VERSION 5.8 ;
BUSBITCHARS "[]" ;
DIVIDERCHAR "/" ;
UNITS
    DATABASE MICRONS 1000 ;
END UNITS

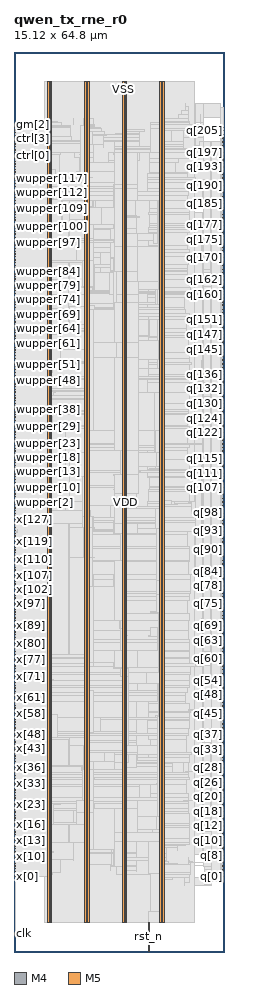
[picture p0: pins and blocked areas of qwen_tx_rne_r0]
MACRO qwen_tx_rne_r0
  FOREIGN qwen_tx_rne_r0 0 0 ;
  CLASS BLOCK ;
  SIZE 15.12 BY 64.8 ;
  PIN clk
    DIRECTION INPUT ;
    USE SIGNAL ;
    PORT
      LAYER M4 ;
        RECT  0.054 1.296 0.138 1.32 ;
    END
    PORT
      LAYER M4 ;
        RECT  0.108 1.296 0.227 1.416 ;
    END
  END clk
  PIN ctrl[0]
    DIRECTION INPUT ;
    USE SIGNAL ;
    PORT
      LAYER M4 ;
        RECT  0.054 57.36 0.138 57.384 ;
    END
  END ctrl[0]
  PIN ctrl[1]
    DIRECTION INPUT ;
    USE SIGNAL ;
    PORT
      LAYER M4 ;
        RECT  0.054 57.552 0.138 57.576 ;
    END
  END ctrl[1]
  PIN ctrl[2]
    DIRECTION INPUT ;
    USE SIGNAL ;
    PORT
      LAYER M4 ;
        RECT  0.054 57.744 0.138 57.768 ;
    END
  END ctrl[2]
  PIN ctrl[3]
    DIRECTION INPUT ;
    USE SIGNAL ;
    PORT
      LAYER M4 ;
        RECT  0.054 57.984 0.138 58.008 ;
    END
  END ctrl[3]
  PIN ctrl[4]
    DIRECTION INPUT ;
    USE SIGNAL ;
    PORT
      LAYER M4 ;
        RECT  0.054 58.176 0.138 58.2 ;
    END
  END ctrl[4]
  PIN ctrl[5]
    DIRECTION INPUT ;
    USE SIGNAL ;
    PORT
      LAYER M4 ;
        RECT  0.054 58.368 0.138 58.392 ;
    END
  END ctrl[5]
  PIN gm[0]
    DIRECTION INPUT ;
    USE SIGNAL ;
    PORT
      LAYER M4 ;
        RECT  0.054 58.56 0.138 58.584 ;
    END
  END gm[0]
  PIN gm[1]
    DIRECTION INPUT ;
    USE SIGNAL ;
    PORT
      LAYER M4 ;
        RECT  0.054 58.8 0.138 58.824 ;
    END
  END gm[1]
  PIN gm[2]
    DIRECTION INPUT ;
    USE SIGNAL ;
    PORT
      LAYER M4 ;
        RECT  0.054 58.992 0.138 59.016 ;
    END
  END gm[2]
  PIN gm[3]
    DIRECTION INPUT ;
    USE SIGNAL ;
    PORT
      LAYER M4 ;
        RECT  0.054 59.184 0.138 59.208 ;
    END
  END gm[3]
  PIN q[0]
    DIRECTION OUTPUT ;
    USE SIGNAL ;
    PORT
      LAYER M4 ;
        RECT  14.982 5.424 15.066 5.448 ;
    END
  END q[0]
  PIN q[100]
    DIRECTION OUTPUT ;
    USE SIGNAL ;
    PORT
      LAYER M4 ;
        RECT  14.982 31.584 15.066 31.608 ;
    END
  END q[100]
  PIN q[101]
    DIRECTION OUTPUT ;
    USE SIGNAL ;
    PORT
      LAYER M4 ;
        RECT  14.982 31.872 15.066 31.896 ;
    END
  END q[101]
  PIN q[102]
    DIRECTION OUTPUT ;
    USE SIGNAL ;
    PORT
      LAYER M4 ;
        RECT  14.982 32.112 15.066 32.136 ;
    END
  END q[102]
  PIN q[103]
    DIRECTION OUTPUT ;
    USE SIGNAL ;
    PORT
      LAYER M4 ;
        RECT  14.982 32.4 15.066 32.424 ;
    END
  END q[103]
  PIN q[104]
    DIRECTION OUTPUT ;
    USE SIGNAL ;
    PORT
      LAYER M4 ;
        RECT  14.982 32.64 15.066 32.664 ;
    END
  END q[104]
  PIN q[105]
    DIRECTION OUTPUT ;
    USE SIGNAL ;
    PORT
      LAYER M4 ;
        RECT  14.982 32.928 15.066 32.952 ;
    END
  END q[105]
  PIN q[106]
    DIRECTION OUTPUT ;
    USE SIGNAL ;
    PORT
      LAYER M4 ;
        RECT  14.982 33.168 15.066 33.192 ;
    END
  END q[106]
  PIN q[107]
    DIRECTION OUTPUT ;
    USE SIGNAL ;
    PORT
      LAYER M4 ;
        RECT  14.982 33.456 15.066 33.48 ;
    END
  END q[107]
  PIN q[108]
    DIRECTION OUTPUT ;
    USE SIGNAL ;
    PORT
      LAYER M4 ;
        RECT  14.982 33.696 15.066 33.72 ;
    END
  END q[108]
  PIN q[109]
    DIRECTION OUTPUT ;
    USE SIGNAL ;
    PORT
      LAYER M4 ;
        RECT  14.982 33.984 15.066 34.008 ;
    END
  END q[109]
  PIN q[10]
    DIRECTION OUTPUT ;
    USE SIGNAL ;
    PORT
      LAYER M4 ;
        RECT  14.982 8.016 15.066 8.04 ;
    END
  END q[10]
  PIN q[110]
    DIRECTION OUTPUT ;
    USE SIGNAL ;
    PORT
      LAYER M4 ;
        RECT  14.982 34.224 15.066 34.248 ;
    END
  END q[110]
  PIN q[111]
    DIRECTION OUTPUT ;
    USE SIGNAL ;
    PORT
      LAYER M4 ;
        RECT  14.982 34.464 15.066 34.488 ;
    END
  END q[111]
  PIN q[112]
    DIRECTION OUTPUT ;
    USE SIGNAL ;
    PORT
      LAYER M4 ;
        RECT  14.982 34.752 15.066 34.776 ;
    END
  END q[112]
  PIN q[113]
    DIRECTION OUTPUT ;
    USE SIGNAL ;
    PORT
      LAYER M4 ;
        RECT  14.982 34.992 15.066 35.016 ;
    END
  END q[113]
  PIN q[114]
    DIRECTION OUTPUT ;
    USE SIGNAL ;
    PORT
      LAYER M4 ;
        RECT  14.982 35.28 15.066 35.304 ;
    END
  END q[114]
  PIN q[115]
    DIRECTION OUTPUT ;
    USE SIGNAL ;
    PORT
      LAYER M4 ;
        RECT  14.982 35.52 15.066 35.544 ;
    END
  END q[115]
  PIN q[116]
    DIRECTION OUTPUT ;
    USE SIGNAL ;
    PORT
      LAYER M4 ;
        RECT  14.982 35.808 15.066 35.832 ;
    END
  END q[116]
  PIN q[117]
    DIRECTION OUTPUT ;
    USE SIGNAL ;
    PORT
      LAYER M4 ;
        RECT  14.982 36.048 15.066 36.072 ;
    END
  END q[117]
  PIN q[118]
    DIRECTION OUTPUT ;
    USE SIGNAL ;
    PORT
      LAYER M4 ;
        RECT  14.982 36.336 15.066 36.36 ;
    END
  END q[118]
  PIN q[119]
    DIRECTION OUTPUT ;
    USE SIGNAL ;
    PORT
      LAYER M4 ;
        RECT  14.982 36.576 15.066 36.6 ;
    END
  END q[119]
  PIN q[11]
    DIRECTION OUTPUT ;
    USE SIGNAL ;
    PORT
      LAYER M4 ;
        RECT  14.982 8.256 15.066 8.28 ;
    END
  END q[11]
  PIN q[120]
    DIRECTION OUTPUT ;
    USE SIGNAL ;
    PORT
      LAYER M4 ;
        RECT  14.982 36.864 15.066 36.888 ;
    END
  END q[120]
  PIN q[121]
    DIRECTION OUTPUT ;
    USE SIGNAL ;
    PORT
      LAYER M4 ;
        RECT  14.982 37.104 15.066 37.128 ;
    END
  END q[121]
  PIN q[122]
    DIRECTION OUTPUT ;
    USE SIGNAL ;
    PORT
      LAYER M4 ;
        RECT  14.982 37.392 15.066 37.416 ;
    END
  END q[122]
  PIN q[123]
    DIRECTION OUTPUT ;
    USE SIGNAL ;
    PORT
      LAYER M4 ;
        RECT  14.982 37.632 15.066 37.656 ;
    END
  END q[123]
  PIN q[124]
    DIRECTION OUTPUT ;
    USE SIGNAL ;
    PORT
      LAYER M4 ;
        RECT  14.982 37.872 15.066 37.896 ;
    END
  END q[124]
  PIN q[125]
    DIRECTION OUTPUT ;
    USE SIGNAL ;
    PORT
      LAYER M4 ;
        RECT  14.982 38.16 15.066 38.184 ;
    END
  END q[125]
  PIN q[126]
    DIRECTION OUTPUT ;
    USE SIGNAL ;
    PORT
      LAYER M4 ;
        RECT  14.982 38.4 15.066 38.424 ;
    END
  END q[126]
  PIN q[127]
    DIRECTION OUTPUT ;
    USE SIGNAL ;
    PORT
      LAYER M4 ;
        RECT  14.982 38.688 15.066 38.712 ;
    END
  END q[127]
  PIN q[128]
    DIRECTION OUTPUT ;
    USE SIGNAL ;
    PORT
      LAYER M4 ;
        RECT  14.982 38.928 15.066 38.952 ;
    END
  END q[128]
  PIN q[129]
    DIRECTION OUTPUT ;
    USE SIGNAL ;
    PORT
      LAYER M4 ;
        RECT  14.982 39.216 15.066 39.24 ;
    END
  END q[129]
  PIN q[12]
    DIRECTION OUTPUT ;
    USE SIGNAL ;
    PORT
      LAYER M4 ;
        RECT  14.982 8.544 15.066 8.568 ;
    END
  END q[12]
  PIN q[130]
    DIRECTION OUTPUT ;
    USE SIGNAL ;
    PORT
      LAYER M4 ;
        RECT  14.982 39.456 15.066 39.48 ;
    END
  END q[130]
  PIN q[131]
    DIRECTION OUTPUT ;
    USE SIGNAL ;
    PORT
      LAYER M4 ;
        RECT  14.982 39.744 15.066 39.768 ;
    END
  END q[131]
  PIN q[132]
    DIRECTION OUTPUT ;
    USE SIGNAL ;
    PORT
      LAYER M4 ;
        RECT  14.982 39.984 15.066 40.008 ;
    END
  END q[132]
  PIN q[133]
    DIRECTION OUTPUT ;
    USE SIGNAL ;
    PORT
      LAYER M4 ;
        RECT  14.982 40.272 15.066 40.296 ;
    END
  END q[133]
  PIN q[134]
    DIRECTION OUTPUT ;
    USE SIGNAL ;
    PORT
      LAYER M4 ;
        RECT  14.982 40.512 15.066 40.536 ;
    END
  END q[134]
  PIN q[135]
    DIRECTION OUTPUT ;
    USE SIGNAL ;
    PORT
      LAYER M4 ;
        RECT  14.982 40.8 15.066 40.824 ;
    END
  END q[135]
  PIN q[136]
    DIRECTION OUTPUT ;
    USE SIGNAL ;
    PORT
      LAYER M4 ;
        RECT  14.982 41.04 15.066 41.064 ;
    END
  END q[136]
  PIN q[137]
    DIRECTION OUTPUT ;
    USE SIGNAL ;
    PORT
      LAYER M4 ;
        RECT  14.982 41.28 15.066 41.304 ;
    END
  END q[137]
  PIN q[138]
    DIRECTION OUTPUT ;
    USE SIGNAL ;
    PORT
      LAYER M4 ;
        RECT  14.982 41.568 15.066 41.592 ;
    END
  END q[138]
  PIN q[139]
    DIRECTION OUTPUT ;
    USE SIGNAL ;
    PORT
      LAYER M4 ;
        RECT  14.982 41.808 15.066 41.832 ;
    END
  END q[139]
  PIN q[13]
    DIRECTION OUTPUT ;
    USE SIGNAL ;
    PORT
      LAYER M4 ;
        RECT  14.982 8.784 15.066 8.808 ;
    END
  END q[13]
  PIN q[140]
    DIRECTION OUTPUT ;
    USE SIGNAL ;
    PORT
      LAYER M4 ;
        RECT  14.982 42.096 15.066 42.12 ;
    END
  END q[140]
  PIN q[141]
    DIRECTION OUTPUT ;
    USE SIGNAL ;
    PORT
      LAYER M4 ;
        RECT  14.982 42.336 15.066 42.36 ;
    END
  END q[141]
  PIN q[142]
    DIRECTION OUTPUT ;
    USE SIGNAL ;
    PORT
      LAYER M4 ;
        RECT  14.982 42.624 15.066 42.648 ;
    END
  END q[142]
  PIN q[143]
    DIRECTION OUTPUT ;
    USE SIGNAL ;
    PORT
      LAYER M4 ;
        RECT  14.982 42.864 15.066 42.888 ;
    END
  END q[143]
  PIN q[144]
    DIRECTION OUTPUT ;
    USE SIGNAL ;
    PORT
      LAYER M4 ;
        RECT  14.982 43.152 15.066 43.176 ;
    END
  END q[144]
  PIN q[145]
    DIRECTION OUTPUT ;
    USE SIGNAL ;
    PORT
      LAYER M4 ;
        RECT  14.982 43.392 15.066 43.416 ;
    END
  END q[145]
  PIN q[146]
    DIRECTION OUTPUT ;
    USE SIGNAL ;
    PORT
      LAYER M4 ;
        RECT  14.982 43.68 15.066 43.704 ;
    END
  END q[146]
  PIN q[147]
    DIRECTION OUTPUT ;
    USE SIGNAL ;
    PORT
      LAYER M4 ;
        RECT  14.982 43.92 15.066 43.944 ;
    END
  END q[147]
  PIN q[148]
    DIRECTION OUTPUT ;
    USE SIGNAL ;
    PORT
      LAYER M4 ;
        RECT  14.982 44.208 15.066 44.232 ;
    END
  END q[148]
  PIN q[149]
    DIRECTION OUTPUT ;
    USE SIGNAL ;
    PORT
      LAYER M4 ;
        RECT  14.982 44.448 15.066 44.472 ;
    END
  END q[149]
  PIN q[14]
    DIRECTION OUTPUT ;
    USE SIGNAL ;
    PORT
      LAYER M4 ;
        RECT  14.982 9.072 15.066 9.096 ;
    END
  END q[14]
  PIN q[150]
    DIRECTION OUTPUT ;
    USE SIGNAL ;
    PORT
      LAYER M4 ;
        RECT  14.982 44.688 15.066 44.712 ;
    END
  END q[150]
  PIN q[151]
    DIRECTION OUTPUT ;
    USE SIGNAL ;
    PORT
      LAYER M4 ;
        RECT  14.982 44.976 15.066 45 ;
    END
  END q[151]
  PIN q[152]
    DIRECTION OUTPUT ;
    USE SIGNAL ;
    PORT
      LAYER M4 ;
        RECT  14.982 45.216 15.066 45.24 ;
    END
  END q[152]
  PIN q[153]
    DIRECTION OUTPUT ;
    USE SIGNAL ;
    PORT
      LAYER M4 ;
        RECT  14.982 45.504 15.066 45.528 ;
    END
  END q[153]
  PIN q[154]
    DIRECTION OUTPUT ;
    USE SIGNAL ;
    PORT
      LAYER M4 ;
        RECT  14.982 45.744 15.066 45.768 ;
    END
  END q[154]
  PIN q[155]
    DIRECTION OUTPUT ;
    USE SIGNAL ;
    PORT
      LAYER M4 ;
        RECT  14.982 46.032 15.066 46.056 ;
    END
  END q[155]
  PIN q[156]
    DIRECTION OUTPUT ;
    USE SIGNAL ;
    PORT
      LAYER M4 ;
        RECT  14.982 46.272 15.066 46.296 ;
    END
  END q[156]
  PIN q[157]
    DIRECTION OUTPUT ;
    USE SIGNAL ;
    PORT
      LAYER M4 ;
        RECT  14.982 46.56 15.066 46.584 ;
    END
  END q[157]
  PIN q[158]
    DIRECTION OUTPUT ;
    USE SIGNAL ;
    PORT
      LAYER M4 ;
        RECT  14.982 46.8 15.066 46.824 ;
    END
  END q[158]
  PIN q[159]
    DIRECTION OUTPUT ;
    USE SIGNAL ;
    PORT
      LAYER M4 ;
        RECT  14.982 47.088 15.066 47.112 ;
    END
  END q[159]
  PIN q[15]
    DIRECTION OUTPUT ;
    USE SIGNAL ;
    PORT
      LAYER M4 ;
        RECT  14.982 9.312 15.066 9.336 ;
    END
  END q[15]
  PIN q[160]
    DIRECTION OUTPUT ;
    USE SIGNAL ;
    PORT
      LAYER M4 ;
        RECT  14.982 47.328 15.066 47.352 ;
    END
  END q[160]
  PIN q[161]
    DIRECTION OUTPUT ;
    USE SIGNAL ;
    PORT
      LAYER M4 ;
        RECT  14.982 47.568 15.066 47.592 ;
    END
  END q[161]
  PIN q[162]
    DIRECTION OUTPUT ;
    USE SIGNAL ;
    PORT
      LAYER M4 ;
        RECT  14.982 47.856 15.066 47.88 ;
    END
  END q[162]
  PIN q[163]
    DIRECTION OUTPUT ;
    USE SIGNAL ;
    PORT
      LAYER M4 ;
        RECT  14.982 48.096 15.066 48.12 ;
    END
  END q[163]
  PIN q[164]
    DIRECTION OUTPUT ;
    USE SIGNAL ;
    PORT
      LAYER M4 ;
        RECT  14.982 48.384 15.066 48.408 ;
    END
  END q[164]
  PIN q[165]
    DIRECTION OUTPUT ;
    USE SIGNAL ;
    PORT
      LAYER M4 ;
        RECT  14.982 48.624 15.066 48.648 ;
    END
  END q[165]
  PIN q[166]
    DIRECTION OUTPUT ;
    USE SIGNAL ;
    PORT
      LAYER M4 ;
        RECT  14.982 48.912 15.066 48.936 ;
    END
  END q[166]
  PIN q[167]
    DIRECTION OUTPUT ;
    USE SIGNAL ;
    PORT
      LAYER M4 ;
        RECT  14.982 49.152 15.066 49.176 ;
    END
  END q[167]
  PIN q[168]
    DIRECTION OUTPUT ;
    USE SIGNAL ;
    PORT
      LAYER M4 ;
        RECT  14.982 49.44 15.066 49.464 ;
    END
  END q[168]
  PIN q[169]
    DIRECTION OUTPUT ;
    USE SIGNAL ;
    PORT
      LAYER M4 ;
        RECT  14.982 49.68 15.066 49.704 ;
    END
  END q[169]
  PIN q[16]
    DIRECTION OUTPUT ;
    USE SIGNAL ;
    PORT
      LAYER M4 ;
        RECT  14.982 9.6 15.066 9.624 ;
    END
  END q[16]
  PIN q[170]
    DIRECTION OUTPUT ;
    USE SIGNAL ;
    PORT
      LAYER M4 ;
        RECT  14.982 49.968 15.066 49.992 ;
    END
  END q[170]
  PIN q[171]
    DIRECTION OUTPUT ;
    USE SIGNAL ;
    PORT
      LAYER M4 ;
        RECT  14.982 50.208 15.066 50.232 ;
    END
  END q[171]
  PIN q[172]
    DIRECTION OUTPUT ;
    USE SIGNAL ;
    PORT
      LAYER M4 ;
        RECT  14.982 50.496 15.066 50.52 ;
    END
  END q[172]
  PIN q[173]
    DIRECTION OUTPUT ;
    USE SIGNAL ;
    PORT
      LAYER M4 ;
        RECT  14.982 50.736 15.066 50.76 ;
    END
  END q[173]
  PIN q[174]
    DIRECTION OUTPUT ;
    USE SIGNAL ;
    PORT
      LAYER M4 ;
        RECT  14.982 50.976 15.066 51 ;
    END
  END q[174]
  PIN q[175]
    DIRECTION OUTPUT ;
    USE SIGNAL ;
    PORT
      LAYER M4 ;
        RECT  14.982 51.264 15.066 51.288 ;
    END
  END q[175]
  PIN q[176]
    DIRECTION OUTPUT ;
    USE SIGNAL ;
    PORT
      LAYER M4 ;
        RECT  14.982 51.504 15.066 51.528 ;
    END
  END q[176]
  PIN q[177]
    DIRECTION OUTPUT ;
    USE SIGNAL ;
    PORT
      LAYER M4 ;
        RECT  14.982 51.792 15.066 51.816 ;
    END
  END q[177]
  PIN q[178]
    DIRECTION OUTPUT ;
    USE SIGNAL ;
    PORT
      LAYER M4 ;
        RECT  14.982 52.032 15.066 52.056 ;
    END
  END q[178]
  PIN q[179]
    DIRECTION OUTPUT ;
    USE SIGNAL ;
    PORT
      LAYER M4 ;
        RECT  14.982 52.32 15.066 52.344 ;
    END
  END q[179]
  PIN q[17]
    DIRECTION OUTPUT ;
    USE SIGNAL ;
    PORT
      LAYER M4 ;
        RECT  14.982 9.84 15.066 9.864 ;
    END
  END q[17]
  PIN q[180]
    DIRECTION OUTPUT ;
    USE SIGNAL ;
    PORT
      LAYER M4 ;
        RECT  14.982 52.56 15.066 52.584 ;
    END
  END q[180]
  PIN q[181]
    DIRECTION OUTPUT ;
    USE SIGNAL ;
    PORT
      LAYER M4 ;
        RECT  14.982 52.848 15.066 52.872 ;
    END
  END q[181]
  PIN q[182]
    DIRECTION OUTPUT ;
    USE SIGNAL ;
    PORT
      LAYER M4 ;
        RECT  14.982 53.088 15.066 53.112 ;
    END
  END q[182]
  PIN q[183]
    DIRECTION OUTPUT ;
    USE SIGNAL ;
    PORT
      LAYER M4 ;
        RECT  14.982 53.376 15.066 53.4 ;
    END
  END q[183]
  PIN q[184]
    DIRECTION OUTPUT ;
    USE SIGNAL ;
    PORT
      LAYER M4 ;
        RECT  14.982 53.616 15.066 53.64 ;
    END
  END q[184]
  PIN q[185]
    DIRECTION OUTPUT ;
    USE SIGNAL ;
    PORT
      LAYER M4 ;
        RECT  14.982 53.904 15.066 53.928 ;
    END
  END q[185]
  PIN q[186]
    DIRECTION OUTPUT ;
    USE SIGNAL ;
    PORT
      LAYER M4 ;
        RECT  14.982 54.144 15.066 54.168 ;
    END
  END q[186]
  PIN q[187]
    DIRECTION OUTPUT ;
    USE SIGNAL ;
    PORT
      LAYER M4 ;
        RECT  14.982 54.384 15.066 54.408 ;
    END
  END q[187]
  PIN q[188]
    DIRECTION OUTPUT ;
    USE SIGNAL ;
    PORT
      LAYER M4 ;
        RECT  14.982 54.672 15.066 54.696 ;
    END
  END q[188]
  PIN q[189]
    DIRECTION OUTPUT ;
    USE SIGNAL ;
    PORT
      LAYER M4 ;
        RECT  14.982 54.912 15.066 54.936 ;
    END
  END q[189]
  PIN q[18]
    DIRECTION OUTPUT ;
    USE SIGNAL ;
    PORT
      LAYER M4 ;
        RECT  14.982 10.128 15.066 10.152 ;
    END
  END q[18]
  PIN q[190]
    DIRECTION OUTPUT ;
    USE SIGNAL ;
    PORT
      LAYER M4 ;
        RECT  14.982 55.2 15.066 55.224 ;
    END
  END q[190]
  PIN q[191]
    DIRECTION OUTPUT ;
    USE SIGNAL ;
    PORT
      LAYER M4 ;
        RECT  14.982 55.44 15.066 55.464 ;
    END
  END q[191]
  PIN q[192]
    DIRECTION OUTPUT ;
    USE SIGNAL ;
    PORT
      LAYER M4 ;
        RECT  14.982 55.728 15.066 55.752 ;
    END
  END q[192]
  PIN q[193]
    DIRECTION OUTPUT ;
    USE SIGNAL ;
    PORT
      LAYER M4 ;
        RECT  14.982 55.968 15.066 55.992 ;
    END
  END q[193]
  PIN q[194]
    DIRECTION OUTPUT ;
    USE SIGNAL ;
    PORT
      LAYER M4 ;
        RECT  14.982 56.256 15.066 56.28 ;
    END
  END q[194]
  PIN q[195]
    DIRECTION OUTPUT ;
    USE SIGNAL ;
    PORT
      LAYER M4 ;
        RECT  14.982 56.496 15.066 56.52 ;
    END
  END q[195]
  PIN q[196]
    DIRECTION OUTPUT ;
    USE SIGNAL ;
    PORT
      LAYER M4 ;
        RECT  14.982 56.784 15.066 56.808 ;
    END
  END q[196]
  PIN q[197]
    DIRECTION OUTPUT ;
    USE SIGNAL ;
    PORT
      LAYER M4 ;
        RECT  14.982 57.024 15.066 57.048 ;
    END
  END q[197]
  PIN q[198]
    DIRECTION OUTPUT ;
    USE SIGNAL ;
    PORT
      LAYER M4 ;
        RECT  14.982 57.312 15.066 57.336 ;
    END
  END q[198]
  PIN q[199]
    DIRECTION OUTPUT ;
    USE SIGNAL ;
    PORT
      LAYER M4 ;
        RECT  14.982 57.552 15.066 57.576 ;
    END
  END q[199]
  PIN q[19]
    DIRECTION OUTPUT ;
    USE SIGNAL ;
    PORT
      LAYER M4 ;
        RECT  14.982 10.368 15.066 10.392 ;
    END
  END q[19]
  PIN q[1]
    DIRECTION OUTPUT ;
    USE SIGNAL ;
    PORT
      LAYER M4 ;
        RECT  14.982 5.664 15.066 5.688 ;
    END
  END q[1]
  PIN q[200]
    DIRECTION OUTPUT ;
    USE SIGNAL ;
    PORT
      LAYER M4 ;
        RECT  14.982 57.792 15.066 57.816 ;
    END
  END q[200]
  PIN q[201]
    DIRECTION OUTPUT ;
    USE SIGNAL ;
    PORT
      LAYER M4 ;
        RECT  14.982 58.08 15.066 58.104 ;
    END
  END q[201]
  PIN q[202]
    DIRECTION OUTPUT ;
    USE SIGNAL ;
    PORT
      LAYER M4 ;
        RECT  14.982 58.32 15.066 58.344 ;
    END
  END q[202]
  PIN q[203]
    DIRECTION OUTPUT ;
    USE SIGNAL ;
    PORT
      LAYER M4 ;
        RECT  14.982 58.608 15.066 58.632 ;
    END
  END q[203]
  PIN q[204]
    DIRECTION OUTPUT ;
    USE SIGNAL ;
    PORT
      LAYER M4 ;
        RECT  14.982 58.848 15.066 58.872 ;
    END
  END q[204]
  PIN q[205]
    DIRECTION OUTPUT ;
    USE SIGNAL ;
    PORT
      LAYER M4 ;
        RECT  14.982 59.136 15.066 59.16 ;
    END
  END q[205]
  PIN q[206]
    DIRECTION OUTPUT ;
    USE SIGNAL ;
    PORT
      LAYER M4 ;
        RECT  14.982 59.376 15.066 59.4 ;
    END
  END q[206]
  PIN q[20]
    DIRECTION OUTPUT ;
    USE SIGNAL ;
    PORT
      LAYER M4 ;
        RECT  14.982 10.608 15.066 10.632 ;
    END
  END q[20]
  PIN q[21]
    DIRECTION OUTPUT ;
    USE SIGNAL ;
    PORT
      LAYER M4 ;
        RECT  14.982 10.896 15.066 10.92 ;
    END
  END q[21]
  PIN q[22]
    DIRECTION OUTPUT ;
    USE SIGNAL ;
    PORT
      LAYER M4 ;
        RECT  14.982 11.136 15.066 11.16 ;
    END
  END q[22]
  PIN q[23]
    DIRECTION OUTPUT ;
    USE SIGNAL ;
    PORT
      LAYER M4 ;
        RECT  14.982 11.424 15.066 11.448 ;
    END
  END q[23]
  PIN q[24]
    DIRECTION OUTPUT ;
    USE SIGNAL ;
    PORT
      LAYER M4 ;
        RECT  14.982 11.664 15.066 11.688 ;
    END
  END q[24]
  PIN q[25]
    DIRECTION OUTPUT ;
    USE SIGNAL ;
    PORT
      LAYER M4 ;
        RECT  14.982 11.952 15.066 11.976 ;
    END
  END q[25]
  PIN q[26]
    DIRECTION OUTPUT ;
    USE SIGNAL ;
    PORT
      LAYER M4 ;
        RECT  14.982 12.192 15.066 12.216 ;
    END
  END q[26]
  PIN q[27]
    DIRECTION OUTPUT ;
    USE SIGNAL ;
    PORT
      LAYER M4 ;
        RECT  14.982 12.48 15.066 12.504 ;
    END
  END q[27]
  PIN q[28]
    DIRECTION OUTPUT ;
    USE SIGNAL ;
    PORT
      LAYER M4 ;
        RECT  14.982 12.72 15.066 12.744 ;
    END
  END q[28]
  PIN q[29]
    DIRECTION OUTPUT ;
    USE SIGNAL ;
    PORT
      LAYER M4 ;
        RECT  14.982 13.008 15.066 13.032 ;
    END
  END q[29]
  PIN q[2]
    DIRECTION OUTPUT ;
    USE SIGNAL ;
    PORT
      LAYER M4 ;
        RECT  14.982 5.904 15.066 5.928 ;
    END
  END q[2]
  PIN q[30]
    DIRECTION OUTPUT ;
    USE SIGNAL ;
    PORT
      LAYER M4 ;
        RECT  14.982 13.248 15.066 13.272 ;
    END
  END q[30]
  PIN q[31]
    DIRECTION OUTPUT ;
    USE SIGNAL ;
    PORT
      LAYER M4 ;
        RECT  14.982 13.536 15.066 13.56 ;
    END
  END q[31]
  PIN q[32]
    DIRECTION OUTPUT ;
    USE SIGNAL ;
    PORT
      LAYER M4 ;
        RECT  14.982 13.776 15.066 13.8 ;
    END
  END q[32]
  PIN q[33]
    DIRECTION OUTPUT ;
    USE SIGNAL ;
    PORT
      LAYER M4 ;
        RECT  14.982 14.016 15.066 14.04 ;
    END
  END q[33]
  PIN q[34]
    DIRECTION OUTPUT ;
    USE SIGNAL ;
    PORT
      LAYER M4 ;
        RECT  14.982 14.304 15.066 14.328 ;
    END
  END q[34]
  PIN q[35]
    DIRECTION OUTPUT ;
    USE SIGNAL ;
    PORT
      LAYER M4 ;
        RECT  14.982 14.544 15.066 14.568 ;
    END
  END q[35]
  PIN q[36]
    DIRECTION OUTPUT ;
    USE SIGNAL ;
    PORT
      LAYER M4 ;
        RECT  14.982 14.832 15.066 14.856 ;
    END
  END q[36]
  PIN q[37]
    DIRECTION OUTPUT ;
    USE SIGNAL ;
    PORT
      LAYER M4 ;
        RECT  14.982 15.072 15.066 15.096 ;
    END
  END q[37]
  PIN q[38]
    DIRECTION OUTPUT ;
    USE SIGNAL ;
    PORT
      LAYER M4 ;
        RECT  14.982 15.36 15.066 15.384 ;
    END
  END q[38]
  PIN q[39]
    DIRECTION OUTPUT ;
    USE SIGNAL ;
    PORT
      LAYER M4 ;
        RECT  14.982 15.6 15.066 15.624 ;
    END
  END q[39]
  PIN q[3]
    DIRECTION OUTPUT ;
    USE SIGNAL ;
    PORT
      LAYER M4 ;
        RECT  14.982 6.192 15.066 6.216 ;
    END
  END q[3]
  PIN q[40]
    DIRECTION OUTPUT ;
    USE SIGNAL ;
    PORT
      LAYER M4 ;
        RECT  14.982 15.888 15.066 15.912 ;
    END
  END q[40]
  PIN q[41]
    DIRECTION OUTPUT ;
    USE SIGNAL ;
    PORT
      LAYER M4 ;
        RECT  14.982 16.128 15.066 16.152 ;
    END
  END q[41]
  PIN q[42]
    DIRECTION OUTPUT ;
    USE SIGNAL ;
    PORT
      LAYER M4 ;
        RECT  14.982 16.416 15.066 16.44 ;
    END
  END q[42]
  PIN q[43]
    DIRECTION OUTPUT ;
    USE SIGNAL ;
    PORT
      LAYER M4 ;
        RECT  14.982 16.656 15.066 16.68 ;
    END
  END q[43]
  PIN q[44]
    DIRECTION OUTPUT ;
    USE SIGNAL ;
    PORT
      LAYER M4 ;
        RECT  14.982 16.944 15.066 16.968 ;
    END
  END q[44]
  PIN q[45]
    DIRECTION OUTPUT ;
    USE SIGNAL ;
    PORT
      LAYER M4 ;
        RECT  14.982 17.184 15.066 17.208 ;
    END
  END q[45]
  PIN q[46]
    DIRECTION OUTPUT ;
    USE SIGNAL ;
    PORT
      LAYER M4 ;
        RECT  14.982 17.424 15.066 17.448 ;
    END
  END q[46]
  PIN q[47]
    DIRECTION OUTPUT ;
    USE SIGNAL ;
    PORT
      LAYER M4 ;
        RECT  14.982 17.712 15.066 17.736 ;
    END
  END q[47]
  PIN q[48]
    DIRECTION OUTPUT ;
    USE SIGNAL ;
    PORT
      LAYER M4 ;
        RECT  14.982 17.952 15.066 17.976 ;
    END
  END q[48]
  PIN q[49]
    DIRECTION OUTPUT ;
    USE SIGNAL ;
    PORT
      LAYER M4 ;
        RECT  14.982 18.24 15.066 18.264 ;
    END
  END q[49]
  PIN q[4]
    DIRECTION OUTPUT ;
    USE SIGNAL ;
    PORT
      LAYER M4 ;
        RECT  14.982 6.432 15.066 6.456 ;
    END
  END q[4]
  PIN q[50]
    DIRECTION OUTPUT ;
    USE SIGNAL ;
    PORT
      LAYER M4 ;
        RECT  14.982 18.48 15.066 18.504 ;
    END
  END q[50]
  PIN q[51]
    DIRECTION OUTPUT ;
    USE SIGNAL ;
    PORT
      LAYER M4 ;
        RECT  14.982 18.768 15.066 18.792 ;
    END
  END q[51]
  PIN q[52]
    DIRECTION OUTPUT ;
    USE SIGNAL ;
    PORT
      LAYER M4 ;
        RECT  14.982 19.008 15.066 19.032 ;
    END
  END q[52]
  PIN q[53]
    DIRECTION OUTPUT ;
    USE SIGNAL ;
    PORT
      LAYER M4 ;
        RECT  14.982 19.296 15.066 19.32 ;
    END
  END q[53]
  PIN q[54]
    DIRECTION OUTPUT ;
    USE SIGNAL ;
    PORT
      LAYER M4 ;
        RECT  14.982 19.536 15.066 19.56 ;
    END
  END q[54]
  PIN q[55]
    DIRECTION OUTPUT ;
    USE SIGNAL ;
    PORT
      LAYER M4 ;
        RECT  14.982 19.824 15.066 19.848 ;
    END
  END q[55]
  PIN q[56]
    DIRECTION OUTPUT ;
    USE SIGNAL ;
    PORT
      LAYER M4 ;
        RECT  14.982 20.064 15.066 20.088 ;
    END
  END q[56]
  PIN q[57]
    DIRECTION OUTPUT ;
    USE SIGNAL ;
    PORT
      LAYER M4 ;
        RECT  14.982 20.352 15.066 20.376 ;
    END
  END q[57]
  PIN q[58]
    DIRECTION OUTPUT ;
    USE SIGNAL ;
    PORT
      LAYER M4 ;
        RECT  14.982 20.592 15.066 20.616 ;
    END
  END q[58]
  PIN q[59]
    DIRECTION OUTPUT ;
    USE SIGNAL ;
    PORT
      LAYER M4 ;
        RECT  14.982 20.832 15.066 20.856 ;
    END
  END q[59]
  PIN q[5]
    DIRECTION OUTPUT ;
    USE SIGNAL ;
    PORT
      LAYER M4 ;
        RECT  14.982 6.72 15.066 6.744 ;
    END
  END q[5]
  PIN q[60]
    DIRECTION OUTPUT ;
    USE SIGNAL ;
    PORT
      LAYER M4 ;
        RECT  14.982 21.12 15.066 21.144 ;
    END
  END q[60]
  PIN q[61]
    DIRECTION OUTPUT ;
    USE SIGNAL ;
    PORT
      LAYER M4 ;
        RECT  14.982 21.36 15.066 21.384 ;
    END
  END q[61]
  PIN q[62]
    DIRECTION OUTPUT ;
    USE SIGNAL ;
    PORT
      LAYER M4 ;
        RECT  14.982 21.648 15.066 21.672 ;
    END
  END q[62]
  PIN q[63]
    DIRECTION OUTPUT ;
    USE SIGNAL ;
    PORT
      LAYER M4 ;
        RECT  14.982 21.888 15.066 21.912 ;
    END
  END q[63]
  PIN q[64]
    DIRECTION OUTPUT ;
    USE SIGNAL ;
    PORT
      LAYER M4 ;
        RECT  14.982 22.176 15.066 22.2 ;
    END
  END q[64]
  PIN q[65]
    DIRECTION OUTPUT ;
    USE SIGNAL ;
    PORT
      LAYER M4 ;
        RECT  14.982 22.416 15.066 22.44 ;
    END
  END q[65]
  PIN q[66]
    DIRECTION OUTPUT ;
    USE SIGNAL ;
    PORT
      LAYER M4 ;
        RECT  14.982 22.704 15.066 22.728 ;
    END
  END q[66]
  PIN q[67]
    DIRECTION OUTPUT ;
    USE SIGNAL ;
    PORT
      LAYER M4 ;
        RECT  14.982 22.944 15.066 22.968 ;
    END
  END q[67]
  PIN q[68]
    DIRECTION OUTPUT ;
    USE SIGNAL ;
    PORT
      LAYER M4 ;
        RECT  14.982 23.232 15.066 23.256 ;
    END
  END q[68]
  PIN q[69]
    DIRECTION OUTPUT ;
    USE SIGNAL ;
    PORT
      LAYER M4 ;
        RECT  14.982 23.472 15.066 23.496 ;
    END
  END q[69]
  PIN q[6]
    DIRECTION OUTPUT ;
    USE SIGNAL ;
    PORT
      LAYER M4 ;
        RECT  14.982 6.96 15.066 6.984 ;
    END
  END q[6]
  PIN q[70]
    DIRECTION OUTPUT ;
    USE SIGNAL ;
    PORT
      LAYER M4 ;
        RECT  14.982 23.76 15.066 23.784 ;
    END
  END q[70]
  PIN q[71]
    DIRECTION OUTPUT ;
    USE SIGNAL ;
    PORT
      LAYER M4 ;
        RECT  14.982 24 15.066 24.024 ;
    END
  END q[71]
  PIN q[72]
    DIRECTION OUTPUT ;
    USE SIGNAL ;
    PORT
      LAYER M4 ;
        RECT  14.982 24.24 15.066 24.264 ;
    END
  END q[72]
  PIN q[73]
    DIRECTION OUTPUT ;
    USE SIGNAL ;
    PORT
      LAYER M4 ;
        RECT  14.982 24.528 15.066 24.552 ;
    END
  END q[73]
  PIN q[74]
    DIRECTION OUTPUT ;
    USE SIGNAL ;
    PORT
      LAYER M4 ;
        RECT  14.982 24.768 15.066 24.792 ;
    END
  END q[74]
  PIN q[75]
    DIRECTION OUTPUT ;
    USE SIGNAL ;
    PORT
      LAYER M4 ;
        RECT  14.982 25.056 15.066 25.08 ;
    END
  END q[75]
  PIN q[76]
    DIRECTION OUTPUT ;
    USE SIGNAL ;
    PORT
      LAYER M4 ;
        RECT  14.982 25.296 15.066 25.32 ;
    END
  END q[76]
  PIN q[77]
    DIRECTION OUTPUT ;
    USE SIGNAL ;
    PORT
      LAYER M4 ;
        RECT  14.982 25.584 15.066 25.608 ;
    END
  END q[77]
  PIN q[78]
    DIRECTION OUTPUT ;
    USE SIGNAL ;
    PORT
      LAYER M4 ;
        RECT  14.982 25.824 15.066 25.848 ;
    END
  END q[78]
  PIN q[79]
    DIRECTION OUTPUT ;
    USE SIGNAL ;
    PORT
      LAYER M4 ;
        RECT  14.982 26.112 15.066 26.136 ;
    END
  END q[79]
  PIN q[7]
    DIRECTION OUTPUT ;
    USE SIGNAL ;
    PORT
      LAYER M4 ;
        RECT  14.982 7.2 15.066 7.224 ;
    END
  END q[7]
  PIN q[80]
    DIRECTION OUTPUT ;
    USE SIGNAL ;
    PORT
      LAYER M4 ;
        RECT  14.982 26.352 15.066 26.376 ;
    END
  END q[80]
  PIN q[81]
    DIRECTION OUTPUT ;
    USE SIGNAL ;
    PORT
      LAYER M4 ;
        RECT  14.982 26.64 15.066 26.664 ;
    END
  END q[81]
  PIN q[82]
    DIRECTION OUTPUT ;
    USE SIGNAL ;
    PORT
      LAYER M4 ;
        RECT  14.982 26.88 15.066 26.904 ;
    END
  END q[82]
  PIN q[83]
    DIRECTION OUTPUT ;
    USE SIGNAL ;
    PORT
      LAYER M4 ;
        RECT  14.982 27.168 15.066 27.192 ;
    END
  END q[83]
  PIN q[84]
    DIRECTION OUTPUT ;
    USE SIGNAL ;
    PORT
      LAYER M4 ;
        RECT  14.982 27.408 15.066 27.432 ;
    END
  END q[84]
  PIN q[85]
    DIRECTION OUTPUT ;
    USE SIGNAL ;
    PORT
      LAYER M4 ;
        RECT  14.982 27.648 15.066 27.672 ;
    END
  END q[85]
  PIN q[86]
    DIRECTION OUTPUT ;
    USE SIGNAL ;
    PORT
      LAYER M4 ;
        RECT  14.982 27.936 15.066 27.96 ;
    END
  END q[86]
  PIN q[87]
    DIRECTION OUTPUT ;
    USE SIGNAL ;
    PORT
      LAYER M4 ;
        RECT  14.982 28.176 15.066 28.2 ;
    END
  END q[87]
  PIN q[88]
    DIRECTION OUTPUT ;
    USE SIGNAL ;
    PORT
      LAYER M4 ;
        RECT  14.982 28.464 15.066 28.488 ;
    END
  END q[88]
  PIN q[89]
    DIRECTION OUTPUT ;
    USE SIGNAL ;
    PORT
      LAYER M4 ;
        RECT  14.982 28.704 15.066 28.728 ;
    END
  END q[89]
  PIN q[8]
    DIRECTION OUTPUT ;
    USE SIGNAL ;
    PORT
      LAYER M4 ;
        RECT  14.982 7.488 15.066 7.512 ;
    END
  END q[8]
  PIN q[90]
    DIRECTION OUTPUT ;
    USE SIGNAL ;
    PORT
      LAYER M4 ;
        RECT  14.982 28.992 15.066 29.016 ;
    END
  END q[90]
  PIN q[91]
    DIRECTION OUTPUT ;
    USE SIGNAL ;
    PORT
      LAYER M4 ;
        RECT  14.982 29.232 15.066 29.256 ;
    END
  END q[91]
  PIN q[92]
    DIRECTION OUTPUT ;
    USE SIGNAL ;
    PORT
      LAYER M4 ;
        RECT  14.982 29.52 15.066 29.544 ;
    END
  END q[92]
  PIN q[93]
    DIRECTION OUTPUT ;
    USE SIGNAL ;
    PORT
      LAYER M4 ;
        RECT  14.982 29.76 15.066 29.784 ;
    END
  END q[93]
  PIN q[94]
    DIRECTION OUTPUT ;
    USE SIGNAL ;
    PORT
      LAYER M4 ;
        RECT  14.982 30.048 15.066 30.072 ;
    END
  END q[94]
  PIN q[95]
    DIRECTION OUTPUT ;
    USE SIGNAL ;
    PORT
      LAYER M4 ;
        RECT  14.982 30.288 15.066 30.312 ;
    END
  END q[95]
  PIN q[96]
    DIRECTION OUTPUT ;
    USE SIGNAL ;
    PORT
      LAYER M4 ;
        RECT  14.982 30.576 15.066 30.6 ;
    END
  END q[96]
  PIN q[97]
    DIRECTION OUTPUT ;
    USE SIGNAL ;
    PORT
      LAYER M4 ;
        RECT  14.982 30.816 15.066 30.84 ;
    END
  END q[97]
  PIN q[98]
    DIRECTION OUTPUT ;
    USE SIGNAL ;
    PORT
      LAYER M4 ;
        RECT  14.982 31.056 15.066 31.08 ;
    END
  END q[98]
  PIN q[99]
    DIRECTION OUTPUT ;
    USE SIGNAL ;
    PORT
      LAYER M4 ;
        RECT  14.982 31.344 15.066 31.368 ;
    END
  END q[99]
  PIN q[9]
    DIRECTION OUTPUT ;
    USE SIGNAL ;
    PORT
      LAYER M4 ;
        RECT  14.982 7.728 15.066 7.752 ;
    END
  END q[9]
  PIN round
    DIRECTION INPUT ;
    USE SIGNAL ;
    PORT
      LAYER M4 ;
        RECT  0.054 59.376 0.138 59.4 ;
    END
  END round
  PIN rst_n
    DIRECTION INPUT ;
    USE SIGNAL ;
    PORT
      LAYER M5 ;
        RECT  9.696 0.054 9.72 0.138 ;
    END
    PORT
      LAYER M5 ;
        RECT  9.696 0.08 9.72 2.137 ;
    END
  END rst_n
  PIN wupper[0]
    DIRECTION INPUT ;
    USE SIGNAL ;
    PORT
      LAYER M4 ;
        RECT  0.054 31.392 0.138 31.416 ;
    END
  END wupper[0]
  PIN wupper[100]
    DIRECTION INPUT ;
    USE SIGNAL ;
    PORT
      LAYER M4 ;
        RECT  0.054 51.696 0.138 51.72 ;
    END
  END wupper[100]
  PIN wupper[101]
    DIRECTION INPUT ;
    USE SIGNAL ;
    PORT
      LAYER M4 ;
        RECT  0.054 51.888 0.138 51.912 ;
    END
  END wupper[101]
  PIN wupper[102]
    DIRECTION INPUT ;
    USE SIGNAL ;
    PORT
      LAYER M4 ;
        RECT  0.054 52.08 0.138 52.104 ;
    END
  END wupper[102]
  PIN wupper[103]
    DIRECTION INPUT ;
    USE SIGNAL ;
    PORT
      LAYER M4 ;
        RECT  0.054 52.272 0.138 52.296 ;
    END
  END wupper[103]
  PIN wupper[104]
    DIRECTION INPUT ;
    USE SIGNAL ;
    PORT
      LAYER M4 ;
        RECT  0.054 52.464 0.138 52.488 ;
    END
  END wupper[104]
  PIN wupper[105]
    DIRECTION INPUT ;
    USE SIGNAL ;
    PORT
      LAYER M4 ;
        RECT  0.054 52.704 0.138 52.728 ;
    END
  END wupper[105]
  PIN wupper[106]
    DIRECTION INPUT ;
    USE SIGNAL ;
    PORT
      LAYER M4 ;
        RECT  0.054 52.896 0.138 52.92 ;
    END
  END wupper[106]
  PIN wupper[107]
    DIRECTION INPUT ;
    USE SIGNAL ;
    PORT
      LAYER M4 ;
        RECT  0.054 53.088 0.138 53.112 ;
    END
  END wupper[107]
  PIN wupper[108]
    DIRECTION INPUT ;
    USE SIGNAL ;
    PORT
      LAYER M4 ;
        RECT  0.054 53.28 0.138 53.304 ;
    END
  END wupper[108]
  PIN wupper[109]
    DIRECTION INPUT ;
    USE SIGNAL ;
    PORT
      LAYER M4 ;
        RECT  0.054 53.52 0.138 53.544 ;
    END
  END wupper[109]
  PIN wupper[10]
    DIRECTION INPUT ;
    USE SIGNAL ;
    PORT
      LAYER M4 ;
        RECT  0.054 33.408 0.138 33.432 ;
    END
  END wupper[10]
  PIN wupper[110]
    DIRECTION INPUT ;
    USE SIGNAL ;
    PORT
      LAYER M4 ;
        RECT  0.054 53.712 0.138 53.736 ;
    END
  END wupper[110]
  PIN wupper[111]
    DIRECTION INPUT ;
    USE SIGNAL ;
    PORT
      LAYER M4 ;
        RECT  0.054 53.904 0.138 53.928 ;
    END
  END wupper[111]
  PIN wupper[112]
    DIRECTION INPUT ;
    USE SIGNAL ;
    PORT
      LAYER M4 ;
        RECT  0.054 54.096 0.138 54.12 ;
    END
  END wupper[112]
  PIN wupper[113]
    DIRECTION INPUT ;
    USE SIGNAL ;
    PORT
      LAYER M4 ;
        RECT  0.054 54.336 0.138 54.36 ;
    END
  END wupper[113]
  PIN wupper[114]
    DIRECTION INPUT ;
    USE SIGNAL ;
    PORT
      LAYER M4 ;
        RECT  0.054 54.528 0.138 54.552 ;
    END
  END wupper[114]
  PIN wupper[115]
    DIRECTION INPUT ;
    USE SIGNAL ;
    PORT
      LAYER M4 ;
        RECT  0.054 54.72 0.138 54.744 ;
    END
  END wupper[115]
  PIN wupper[116]
    DIRECTION INPUT ;
    USE SIGNAL ;
    PORT
      LAYER M4 ;
        RECT  0.054 54.912 0.138 54.936 ;
    END
  END wupper[116]
  PIN wupper[117]
    DIRECTION INPUT ;
    USE SIGNAL ;
    PORT
      LAYER M4 ;
        RECT  0.054 55.104 0.138 55.128 ;
    END
  END wupper[117]
  PIN wupper[118]
    DIRECTION INPUT ;
    USE SIGNAL ;
    PORT
      LAYER M4 ;
        RECT  0.054 55.344 0.138 55.368 ;
    END
  END wupper[118]
  PIN wupper[119]
    DIRECTION INPUT ;
    USE SIGNAL ;
    PORT
      LAYER M4 ;
        RECT  0.054 55.536 0.138 55.56 ;
    END
  END wupper[119]
  PIN wupper[11]
    DIRECTION INPUT ;
    USE SIGNAL ;
    PORT
      LAYER M4 ;
        RECT  0.054 33.6 0.138 33.624 ;
    END
  END wupper[11]
  PIN wupper[120]
    DIRECTION INPUT ;
    USE SIGNAL ;
    PORT
      LAYER M4 ;
        RECT  0.054 55.728 0.138 55.752 ;
    END
  END wupper[120]
  PIN wupper[121]
    DIRECTION INPUT ;
    USE SIGNAL ;
    PORT
      LAYER M4 ;
        RECT  0.054 55.92 0.138 55.944 ;
    END
  END wupper[121]
  PIN wupper[122]
    DIRECTION INPUT ;
    USE SIGNAL ;
    PORT
      LAYER M4 ;
        RECT  0.054 56.16 0.138 56.184 ;
    END
  END wupper[122]
  PIN wupper[123]
    DIRECTION INPUT ;
    USE SIGNAL ;
    PORT
      LAYER M4 ;
        RECT  0.054 56.352 0.138 56.376 ;
    END
  END wupper[123]
  PIN wupper[124]
    DIRECTION INPUT ;
    USE SIGNAL ;
    PORT
      LAYER M4 ;
        RECT  0.054 56.544 0.138 56.568 ;
    END
  END wupper[124]
  PIN wupper[125]
    DIRECTION INPUT ;
    USE SIGNAL ;
    PORT
      LAYER M4 ;
        RECT  0.054 56.736 0.138 56.76 ;
    END
  END wupper[125]
  PIN wupper[126]
    DIRECTION INPUT ;
    USE SIGNAL ;
    PORT
      LAYER M4 ;
        RECT  0.054 56.928 0.138 56.952 ;
    END
  END wupper[126]
  PIN wupper[127]
    DIRECTION INPUT ;
    USE SIGNAL ;
    PORT
      LAYER M4 ;
        RECT  0.054 57.168 0.138 57.192 ;
    END
  END wupper[127]
  PIN wupper[12]
    DIRECTION INPUT ;
    USE SIGNAL ;
    PORT
      LAYER M4 ;
        RECT  0.054 33.792 0.138 33.816 ;
    END
  END wupper[12]
  PIN wupper[13]
    DIRECTION INPUT ;
    USE SIGNAL ;
    PORT
      LAYER M4 ;
        RECT  0.054 34.032 0.138 34.056 ;
    END
  END wupper[13]
  PIN wupper[14]
    DIRECTION INPUT ;
    USE SIGNAL ;
    PORT
      LAYER M4 ;
        RECT  0.054 34.224 0.138 34.248 ;
    END
  END wupper[14]
  PIN wupper[15]
    DIRECTION INPUT ;
    USE SIGNAL ;
    PORT
      LAYER M4 ;
        RECT  0.054 34.416 0.138 34.44 ;
    END
  END wupper[15]
  PIN wupper[16]
    DIRECTION INPUT ;
    USE SIGNAL ;
    PORT
      LAYER M4 ;
        RECT  0.054 34.608 0.138 34.632 ;
    END
  END wupper[16]
  PIN wupper[17]
    DIRECTION INPUT ;
    USE SIGNAL ;
    PORT
      LAYER M4 ;
        RECT  0.054 34.848 0.138 34.872 ;
    END
  END wupper[17]
  PIN wupper[18]
    DIRECTION INPUT ;
    USE SIGNAL ;
    PORT
      LAYER M4 ;
        RECT  0.054 35.04 0.138 35.064 ;
    END
  END wupper[18]
  PIN wupper[19]
    DIRECTION INPUT ;
    USE SIGNAL ;
    PORT
      LAYER M4 ;
        RECT  0.054 35.232 0.138 35.256 ;
    END
  END wupper[19]
  PIN wupper[1]
    DIRECTION INPUT ;
    USE SIGNAL ;
    PORT
      LAYER M4 ;
        RECT  0.054 31.584 0.138 31.608 ;
    END
  END wupper[1]
  PIN wupper[20]
    DIRECTION INPUT ;
    USE SIGNAL ;
    PORT
      LAYER M4 ;
        RECT  0.054 35.424 0.138 35.448 ;
    END
  END wupper[20]
  PIN wupper[21]
    DIRECTION INPUT ;
    USE SIGNAL ;
    PORT
      LAYER M4 ;
        RECT  0.054 35.616 0.138 35.64 ;
    END
  END wupper[21]
  PIN wupper[22]
    DIRECTION INPUT ;
    USE SIGNAL ;
    PORT
      LAYER M4 ;
        RECT  0.054 35.856 0.138 35.88 ;
    END
  END wupper[22]
  PIN wupper[23]
    DIRECTION INPUT ;
    USE SIGNAL ;
    PORT
      LAYER M4 ;
        RECT  0.054 36.048 0.138 36.072 ;
    END
  END wupper[23]
  PIN wupper[24]
    DIRECTION INPUT ;
    USE SIGNAL ;
    PORT
      LAYER M4 ;
        RECT  0.054 36.24 0.138 36.264 ;
    END
  END wupper[24]
  PIN wupper[25]
    DIRECTION INPUT ;
    USE SIGNAL ;
    PORT
      LAYER M4 ;
        RECT  0.054 36.432 0.138 36.456 ;
    END
  END wupper[25]
  PIN wupper[26]
    DIRECTION INPUT ;
    USE SIGNAL ;
    PORT
      LAYER M4 ;
        RECT  0.054 36.672 0.138 36.696 ;
    END
  END wupper[26]
  PIN wupper[27]
    DIRECTION INPUT ;
    USE SIGNAL ;
    PORT
      LAYER M4 ;
        RECT  0.054 36.864 0.138 36.888 ;
    END
  END wupper[27]
  PIN wupper[28]
    DIRECTION INPUT ;
    USE SIGNAL ;
    PORT
      LAYER M4 ;
        RECT  0.054 37.056 0.138 37.08 ;
    END
  END wupper[28]
  PIN wupper[29]
    DIRECTION INPUT ;
    USE SIGNAL ;
    PORT
      LAYER M4 ;
        RECT  0.054 37.248 0.138 37.272 ;
    END
  END wupper[29]
  PIN wupper[2]
    DIRECTION INPUT ;
    USE SIGNAL ;
    PORT
      LAYER M4 ;
        RECT  0.054 31.776 0.138 31.8 ;
    END
  END wupper[2]
  PIN wupper[30]
    DIRECTION INPUT ;
    USE SIGNAL ;
    PORT
      LAYER M4 ;
        RECT  0.054 37.44 0.138 37.464 ;
    END
  END wupper[30]
  PIN wupper[31]
    DIRECTION INPUT ;
    USE SIGNAL ;
    PORT
      LAYER M4 ;
        RECT  0.054 37.68 0.138 37.704 ;
    END
  END wupper[31]
  PIN wupper[32]
    DIRECTION INPUT ;
    USE SIGNAL ;
    PORT
      LAYER M4 ;
        RECT  0.054 37.872 0.138 37.896 ;
    END
  END wupper[32]
  PIN wupper[33]
    DIRECTION INPUT ;
    USE SIGNAL ;
    PORT
      LAYER M4 ;
        RECT  0.054 38.064 0.138 38.088 ;
    END
  END wupper[33]
  PIN wupper[34]
    DIRECTION INPUT ;
    USE SIGNAL ;
    PORT
      LAYER M4 ;
        RECT  0.054 38.256 0.138 38.28 ;
    END
  END wupper[34]
  PIN wupper[35]
    DIRECTION INPUT ;
    USE SIGNAL ;
    PORT
      LAYER M4 ;
        RECT  0.054 38.496 0.138 38.52 ;
    END
  END wupper[35]
  PIN wupper[36]
    DIRECTION INPUT ;
    USE SIGNAL ;
    PORT
      LAYER M4 ;
        RECT  0.054 38.688 0.138 38.712 ;
    END
  END wupper[36]
  PIN wupper[37]
    DIRECTION INPUT ;
    USE SIGNAL ;
    PORT
      LAYER M4 ;
        RECT  0.054 38.88 0.138 38.904 ;
    END
  END wupper[37]
  PIN wupper[38]
    DIRECTION INPUT ;
    USE SIGNAL ;
    PORT
      LAYER M4 ;
        RECT  0.054 39.072 0.138 39.096 ;
    END
  END wupper[38]
  PIN wupper[39]
    DIRECTION INPUT ;
    USE SIGNAL ;
    PORT
      LAYER M4 ;
        RECT  0.054 39.312 0.138 39.336 ;
    END
  END wupper[39]
  PIN wupper[3]
    DIRECTION INPUT ;
    USE SIGNAL ;
    PORT
      LAYER M4 ;
        RECT  0.054 31.968 0.138 31.992 ;
    END
  END wupper[3]
  PIN wupper[40]
    DIRECTION INPUT ;
    USE SIGNAL ;
    PORT
      LAYER M4 ;
        RECT  0.054 39.504 0.138 39.528 ;
    END
  END wupper[40]
  PIN wupper[41]
    DIRECTION INPUT ;
    USE SIGNAL ;
    PORT
      LAYER M4 ;
        RECT  0.054 39.696 0.138 39.72 ;
    END
  END wupper[41]
  PIN wupper[42]
    DIRECTION INPUT ;
    USE SIGNAL ;
    PORT
      LAYER M4 ;
        RECT  0.054 39.888 0.138 39.912 ;
    END
  END wupper[42]
  PIN wupper[43]
    DIRECTION INPUT ;
    USE SIGNAL ;
    PORT
      LAYER M4 ;
        RECT  0.054 40.08 0.138 40.104 ;
    END
  END wupper[43]
  PIN wupper[44]
    DIRECTION INPUT ;
    USE SIGNAL ;
    PORT
      LAYER M4 ;
        RECT  0.054 40.32 0.138 40.344 ;
    END
  END wupper[44]
  PIN wupper[45]
    DIRECTION INPUT ;
    USE SIGNAL ;
    PORT
      LAYER M4 ;
        RECT  0.054 40.512 0.138 40.536 ;
    END
  END wupper[45]
  PIN wupper[46]
    DIRECTION INPUT ;
    USE SIGNAL ;
    PORT
      LAYER M4 ;
        RECT  0.054 40.704 0.138 40.728 ;
    END
  END wupper[46]
  PIN wupper[47]
    DIRECTION INPUT ;
    USE SIGNAL ;
    PORT
      LAYER M4 ;
        RECT  0.054 40.896 0.138 40.92 ;
    END
  END wupper[47]
  PIN wupper[48]
    DIRECTION INPUT ;
    USE SIGNAL ;
    PORT
      LAYER M4 ;
        RECT  0.054 41.136 0.138 41.16 ;
    END
  END wupper[48]
  PIN wupper[49]
    DIRECTION INPUT ;
    USE SIGNAL ;
    PORT
      LAYER M4 ;
        RECT  0.054 41.328 0.138 41.352 ;
    END
  END wupper[49]
  PIN wupper[4]
    DIRECTION INPUT ;
    USE SIGNAL ;
    PORT
      LAYER M4 ;
        RECT  0.054 32.208 0.138 32.232 ;
    END
  END wupper[4]
  PIN wupper[50]
    DIRECTION INPUT ;
    USE SIGNAL ;
    PORT
      LAYER M4 ;
        RECT  0.054 41.52 0.138 41.544 ;
    END
  END wupper[50]
  PIN wupper[51]
    DIRECTION INPUT ;
    USE SIGNAL ;
    PORT
      LAYER M4 ;
        RECT  0.054 41.712 0.138 41.736 ;
    END
  END wupper[51]
  PIN wupper[52]
    DIRECTION INPUT ;
    USE SIGNAL ;
    PORT
      LAYER M4 ;
        RECT  0.054 41.952 0.138 41.976 ;
    END
  END wupper[52]
  PIN wupper[53]
    DIRECTION INPUT ;
    USE SIGNAL ;
    PORT
      LAYER M4 ;
        RECT  0.054 42.144 0.138 42.168 ;
    END
  END wupper[53]
  PIN wupper[54]
    DIRECTION INPUT ;
    USE SIGNAL ;
    PORT
      LAYER M4 ;
        RECT  0.054 42.336 0.138 42.36 ;
    END
  END wupper[54]
  PIN wupper[55]
    DIRECTION INPUT ;
    USE SIGNAL ;
    PORT
      LAYER M4 ;
        RECT  0.054 42.528 0.138 42.552 ;
    END
  END wupper[55]
  PIN wupper[56]
    DIRECTION INPUT ;
    USE SIGNAL ;
    PORT
      LAYER M4 ;
        RECT  0.054 42.72 0.138 42.744 ;
    END
  END wupper[56]
  PIN wupper[57]
    DIRECTION INPUT ;
    USE SIGNAL ;
    PORT
      LAYER M4 ;
        RECT  0.054 42.96 0.138 42.984 ;
    END
  END wupper[57]
  PIN wupper[58]
    DIRECTION INPUT ;
    USE SIGNAL ;
    PORT
      LAYER M4 ;
        RECT  0.054 43.152 0.138 43.176 ;
    END
  END wupper[58]
  PIN wupper[59]
    DIRECTION INPUT ;
    USE SIGNAL ;
    PORT
      LAYER M4 ;
        RECT  0.054 43.344 0.138 43.368 ;
    END
  END wupper[59]
  PIN wupper[5]
    DIRECTION INPUT ;
    USE SIGNAL ;
    PORT
      LAYER M4 ;
        RECT  0.054 32.4 0.138 32.424 ;
    END
  END wupper[5]
  PIN wupper[60]
    DIRECTION INPUT ;
    USE SIGNAL ;
    PORT
      LAYER M4 ;
        RECT  0.054 43.536 0.138 43.56 ;
    END
  END wupper[60]
  PIN wupper[61]
    DIRECTION INPUT ;
    USE SIGNAL ;
    PORT
      LAYER M4 ;
        RECT  0.054 43.776 0.138 43.8 ;
    END
  END wupper[61]
  PIN wupper[62]
    DIRECTION INPUT ;
    USE SIGNAL ;
    PORT
      LAYER M4 ;
        RECT  0.054 43.968 0.138 43.992 ;
    END
  END wupper[62]
  PIN wupper[63]
    DIRECTION INPUT ;
    USE SIGNAL ;
    PORT
      LAYER M4 ;
        RECT  0.054 44.16 0.138 44.184 ;
    END
  END wupper[63]
  PIN wupper[64]
    DIRECTION INPUT ;
    USE SIGNAL ;
    PORT
      LAYER M4 ;
        RECT  0.054 44.352 0.138 44.376 ;
    END
  END wupper[64]
  PIN wupper[65]
    DIRECTION INPUT ;
    USE SIGNAL ;
    PORT
      LAYER M4 ;
        RECT  0.054 44.592 0.138 44.616 ;
    END
  END wupper[65]
  PIN wupper[66]
    DIRECTION INPUT ;
    USE SIGNAL ;
    PORT
      LAYER M4 ;
        RECT  0.054 44.784 0.138 44.808 ;
    END
  END wupper[66]
  PIN wupper[67]
    DIRECTION INPUT ;
    USE SIGNAL ;
    PORT
      LAYER M4 ;
        RECT  0.054 44.976 0.138 45 ;
    END
  END wupper[67]
  PIN wupper[68]
    DIRECTION INPUT ;
    USE SIGNAL ;
    PORT
      LAYER M4 ;
        RECT  0.054 45.168 0.138 45.192 ;
    END
  END wupper[68]
  PIN wupper[69]
    DIRECTION INPUT ;
    USE SIGNAL ;
    PORT
      LAYER M4 ;
        RECT  0.054 45.36 0.138 45.384 ;
    END
  END wupper[69]
  PIN wupper[6]
    DIRECTION INPUT ;
    USE SIGNAL ;
    PORT
      LAYER M4 ;
        RECT  0.054 32.592 0.138 32.616 ;
    END
  END wupper[6]
  PIN wupper[70]
    DIRECTION INPUT ;
    USE SIGNAL ;
    PORT
      LAYER M4 ;
        RECT  0.054 45.6 0.138 45.624 ;
    END
  END wupper[70]
  PIN wupper[71]
    DIRECTION INPUT ;
    USE SIGNAL ;
    PORT
      LAYER M4 ;
        RECT  0.054 45.792 0.138 45.816 ;
    END
  END wupper[71]
  PIN wupper[72]
    DIRECTION INPUT ;
    USE SIGNAL ;
    PORT
      LAYER M4 ;
        RECT  0.054 45.984 0.138 46.008 ;
    END
  END wupper[72]
  PIN wupper[73]
    DIRECTION INPUT ;
    USE SIGNAL ;
    PORT
      LAYER M4 ;
        RECT  0.054 46.176 0.138 46.2 ;
    END
  END wupper[73]
  PIN wupper[74]
    DIRECTION INPUT ;
    USE SIGNAL ;
    PORT
      LAYER M4 ;
        RECT  0.054 46.416 0.138 46.44 ;
    END
  END wupper[74]
  PIN wupper[75]
    DIRECTION INPUT ;
    USE SIGNAL ;
    PORT
      LAYER M4 ;
        RECT  0.054 46.608 0.138 46.632 ;
    END
  END wupper[75]
  PIN wupper[76]
    DIRECTION INPUT ;
    USE SIGNAL ;
    PORT
      LAYER M4 ;
        RECT  0.054 46.8 0.138 46.824 ;
    END
  END wupper[76]
  PIN wupper[77]
    DIRECTION INPUT ;
    USE SIGNAL ;
    PORT
      LAYER M4 ;
        RECT  0.054 46.992 0.138 47.016 ;
    END
  END wupper[77]
  PIN wupper[78]
    DIRECTION INPUT ;
    USE SIGNAL ;
    PORT
      LAYER M4 ;
        RECT  0.054 47.184 0.138 47.208 ;
    END
  END wupper[78]
  PIN wupper[79]
    DIRECTION INPUT ;
    USE SIGNAL ;
    PORT
      LAYER M4 ;
        RECT  0.054 47.424 0.138 47.448 ;
    END
  END wupper[79]
  PIN wupper[7]
    DIRECTION INPUT ;
    USE SIGNAL ;
    PORT
      LAYER M4 ;
        RECT  0.054 32.784 0.138 32.808 ;
    END
  END wupper[7]
  PIN wupper[80]
    DIRECTION INPUT ;
    USE SIGNAL ;
    PORT
      LAYER M4 ;
        RECT  0.054 47.616 0.138 47.64 ;
    END
  END wupper[80]
  PIN wupper[81]
    DIRECTION INPUT ;
    USE SIGNAL ;
    PORT
      LAYER M4 ;
        RECT  0.054 47.808 0.138 47.832 ;
    END
  END wupper[81]
  PIN wupper[82]
    DIRECTION INPUT ;
    USE SIGNAL ;
    PORT
      LAYER M4 ;
        RECT  0.054 48 0.138 48.024 ;
    END
  END wupper[82]
  PIN wupper[83]
    DIRECTION INPUT ;
    USE SIGNAL ;
    PORT
      LAYER M4 ;
        RECT  0.054 48.24 0.138 48.264 ;
    END
  END wupper[83]
  PIN wupper[84]
    DIRECTION INPUT ;
    USE SIGNAL ;
    PORT
      LAYER M4 ;
        RECT  0.054 48.432 0.138 48.456 ;
    END
  END wupper[84]
  PIN wupper[85]
    DIRECTION INPUT ;
    USE SIGNAL ;
    PORT
      LAYER M4 ;
        RECT  0.054 48.624 0.138 48.648 ;
    END
  END wupper[85]
  PIN wupper[86]
    DIRECTION INPUT ;
    USE SIGNAL ;
    PORT
      LAYER M4 ;
        RECT  0.054 48.816 0.138 48.84 ;
    END
  END wupper[86]
  PIN wupper[87]
    DIRECTION INPUT ;
    USE SIGNAL ;
    PORT
      LAYER M4 ;
        RECT  0.054 49.056 0.138 49.08 ;
    END
  END wupper[87]
  PIN wupper[88]
    DIRECTION INPUT ;
    USE SIGNAL ;
    PORT
      LAYER M4 ;
        RECT  0.054 49.248 0.138 49.272 ;
    END
  END wupper[88]
  PIN wupper[89]
    DIRECTION INPUT ;
    USE SIGNAL ;
    PORT
      LAYER M4 ;
        RECT  0.054 49.44 0.138 49.464 ;
    END
  END wupper[89]
  PIN wupper[8]
    DIRECTION INPUT ;
    USE SIGNAL ;
    PORT
      LAYER M4 ;
        RECT  0.054 32.976 0.138 33 ;
    END
  END wupper[8]
  PIN wupper[90]
    DIRECTION INPUT ;
    USE SIGNAL ;
    PORT
      LAYER M4 ;
        RECT  0.054 49.632 0.138 49.656 ;
    END
  END wupper[90]
  PIN wupper[91]
    DIRECTION INPUT ;
    USE SIGNAL ;
    PORT
      LAYER M4 ;
        RECT  0.054 49.824 0.138 49.848 ;
    END
  END wupper[91]
  PIN wupper[92]
    DIRECTION INPUT ;
    USE SIGNAL ;
    PORT
      LAYER M4 ;
        RECT  0.054 50.064 0.138 50.088 ;
    END
  END wupper[92]
  PIN wupper[93]
    DIRECTION INPUT ;
    USE SIGNAL ;
    PORT
      LAYER M4 ;
        RECT  0.054 50.256 0.138 50.28 ;
    END
  END wupper[93]
  PIN wupper[94]
    DIRECTION INPUT ;
    USE SIGNAL ;
    PORT
      LAYER M4 ;
        RECT  0.054 50.448 0.138 50.472 ;
    END
  END wupper[94]
  PIN wupper[95]
    DIRECTION INPUT ;
    USE SIGNAL ;
    PORT
      LAYER M4 ;
        RECT  0.054 50.64 0.138 50.664 ;
    END
  END wupper[95]
  PIN wupper[96]
    DIRECTION INPUT ;
    USE SIGNAL ;
    PORT
      LAYER M4 ;
        RECT  0.054 50.88 0.138 50.904 ;
    END
  END wupper[96]
  PIN wupper[97]
    DIRECTION INPUT ;
    USE SIGNAL ;
    PORT
      LAYER M4 ;
        RECT  0.054 51.072 0.138 51.096 ;
    END
  END wupper[97]
  PIN wupper[98]
    DIRECTION INPUT ;
    USE SIGNAL ;
    PORT
      LAYER M4 ;
        RECT  0.054 51.264 0.138 51.288 ;
    END
  END wupper[98]
  PIN wupper[99]
    DIRECTION INPUT ;
    USE SIGNAL ;
    PORT
      LAYER M4 ;
        RECT  0.054 51.456 0.138 51.48 ;
    END
  END wupper[99]
  PIN wupper[9]
    DIRECTION INPUT ;
    USE SIGNAL ;
    PORT
      LAYER M4 ;
        RECT  0.054 33.216 0.138 33.24 ;
    END
  END wupper[9]
  PIN x[0]
    DIRECTION INPUT ;
    USE SIGNAL ;
    PORT
      LAYER M4 ;
        RECT  0.054 5.424 0.138 5.448 ;
    END
  END x[0]
  PIN x[100]
    DIRECTION INPUT ;
    USE SIGNAL ;
    PORT
      LAYER M4 ;
        RECT  0.054 25.68 0.138 25.704 ;
    END
  END x[100]
  PIN x[101]
    DIRECTION INPUT ;
    USE SIGNAL ;
    PORT
      LAYER M4 ;
        RECT  0.054 25.872 0.138 25.896 ;
    END
  END x[101]
  PIN x[102]
    DIRECTION INPUT ;
    USE SIGNAL ;
    PORT
      LAYER M4 ;
        RECT  0.054 26.112 0.138 26.136 ;
    END
  END x[102]
  PIN x[103]
    DIRECTION INPUT ;
    USE SIGNAL ;
    PORT
      LAYER M4 ;
        RECT  0.054 26.304 0.138 26.328 ;
    END
  END x[103]
  PIN x[104]
    DIRECTION INPUT ;
    USE SIGNAL ;
    PORT
      LAYER M4 ;
        RECT  0.054 26.496 0.138 26.52 ;
    END
  END x[104]
  PIN x[105]
    DIRECTION INPUT ;
    USE SIGNAL ;
    PORT
      LAYER M4 ;
        RECT  0.054 26.688 0.138 26.712 ;
    END
  END x[105]
  PIN x[106]
    DIRECTION INPUT ;
    USE SIGNAL ;
    PORT
      LAYER M4 ;
        RECT  0.054 26.928 0.138 26.952 ;
    END
  END x[106]
  PIN x[107]
    DIRECTION INPUT ;
    USE SIGNAL ;
    PORT
      LAYER M4 ;
        RECT  0.054 27.12 0.138 27.144 ;
    END
  END x[107]
  PIN x[108]
    DIRECTION INPUT ;
    USE SIGNAL ;
    PORT
      LAYER M4 ;
        RECT  0.054 27.312 0.138 27.336 ;
    END
  END x[108]
  PIN x[109]
    DIRECTION INPUT ;
    USE SIGNAL ;
    PORT
      LAYER M4 ;
        RECT  0.054 27.504 0.138 27.528 ;
    END
  END x[109]
  PIN x[10]
    DIRECTION INPUT ;
    USE SIGNAL ;
    PORT
      LAYER M4 ;
        RECT  0.054 7.44 0.138 7.464 ;
    END
  END x[10]
  PIN x[110]
    DIRECTION INPUT ;
    USE SIGNAL ;
    PORT
      LAYER M4 ;
        RECT  0.054 27.696 0.138 27.72 ;
    END
  END x[110]
  PIN x[111]
    DIRECTION INPUT ;
    USE SIGNAL ;
    PORT
      LAYER M4 ;
        RECT  0.054 27.936 0.138 27.96 ;
    END
  END x[111]
  PIN x[112]
    DIRECTION INPUT ;
    USE SIGNAL ;
    PORT
      LAYER M4 ;
        RECT  0.054 28.128 0.138 28.152 ;
    END
  END x[112]
  PIN x[113]
    DIRECTION INPUT ;
    USE SIGNAL ;
    PORT
      LAYER M4 ;
        RECT  0.054 28.32 0.138 28.344 ;
    END
  END x[113]
  PIN x[114]
    DIRECTION INPUT ;
    USE SIGNAL ;
    PORT
      LAYER M4 ;
        RECT  0.054 28.512 0.138 28.536 ;
    END
  END x[114]
  PIN x[115]
    DIRECTION INPUT ;
    USE SIGNAL ;
    PORT
      LAYER M4 ;
        RECT  0.054 28.752 0.138 28.776 ;
    END
  END x[115]
  PIN x[116]
    DIRECTION INPUT ;
    USE SIGNAL ;
    PORT
      LAYER M4 ;
        RECT  0.054 28.944 0.138 28.968 ;
    END
  END x[116]
  PIN x[117]
    DIRECTION INPUT ;
    USE SIGNAL ;
    PORT
      LAYER M4 ;
        RECT  0.054 29.136 0.138 29.16 ;
    END
  END x[117]
  PIN x[118]
    DIRECTION INPUT ;
    USE SIGNAL ;
    PORT
      LAYER M4 ;
        RECT  0.054 29.328 0.138 29.352 ;
    END
  END x[118]
  PIN x[119]
    DIRECTION INPUT ;
    USE SIGNAL ;
    PORT
      LAYER M4 ;
        RECT  0.054 29.568 0.138 29.592 ;
    END
  END x[119]
  PIN x[11]
    DIRECTION INPUT ;
    USE SIGNAL ;
    PORT
      LAYER M4 ;
        RECT  0.054 7.632 0.138 7.656 ;
    END
  END x[11]
  PIN x[120]
    DIRECTION INPUT ;
    USE SIGNAL ;
    PORT
      LAYER M4 ;
        RECT  0.054 29.76 0.138 29.784 ;
    END
  END x[120]
  PIN x[121]
    DIRECTION INPUT ;
    USE SIGNAL ;
    PORT
      LAYER M4 ;
        RECT  0.054 29.952 0.138 29.976 ;
    END
  END x[121]
  PIN x[122]
    DIRECTION INPUT ;
    USE SIGNAL ;
    PORT
      LAYER M4 ;
        RECT  0.054 30.144 0.138 30.168 ;
    END
  END x[122]
  PIN x[123]
    DIRECTION INPUT ;
    USE SIGNAL ;
    PORT
      LAYER M4 ;
        RECT  0.054 30.336 0.138 30.36 ;
    END
  END x[123]
  PIN x[124]
    DIRECTION INPUT ;
    USE SIGNAL ;
    PORT
      LAYER M4 ;
        RECT  0.054 30.576 0.138 30.6 ;
    END
  END x[124]
  PIN x[125]
    DIRECTION INPUT ;
    USE SIGNAL ;
    PORT
      LAYER M4 ;
        RECT  0.054 30.768 0.138 30.792 ;
    END
  END x[125]
  PIN x[126]
    DIRECTION INPUT ;
    USE SIGNAL ;
    PORT
      LAYER M4 ;
        RECT  0.054 30.96 0.138 30.984 ;
    END
  END x[126]
  PIN x[127]
    DIRECTION INPUT ;
    USE SIGNAL ;
    PORT
      LAYER M4 ;
        RECT  0.054 31.152 0.138 31.176 ;
    END
  END x[127]
  PIN x[12]
    DIRECTION INPUT ;
    USE SIGNAL ;
    PORT
      LAYER M4 ;
        RECT  0.054 7.824 0.138 7.848 ;
    END
  END x[12]
  PIN x[13]
    DIRECTION INPUT ;
    USE SIGNAL ;
    PORT
      LAYER M4 ;
        RECT  0.054 8.016 0.138 8.04 ;
    END
  END x[13]
  PIN x[14]
    DIRECTION INPUT ;
    USE SIGNAL ;
    PORT
      LAYER M4 ;
        RECT  0.054 8.208 0.138 8.232 ;
    END
  END x[14]
  PIN x[15]
    DIRECTION INPUT ;
    USE SIGNAL ;
    PORT
      LAYER M4 ;
        RECT  0.054 8.448 0.138 8.472 ;
    END
  END x[15]
  PIN x[16]
    DIRECTION INPUT ;
    USE SIGNAL ;
    PORT
      LAYER M4 ;
        RECT  0.054 8.64 0.138 8.664 ;
    END
  END x[16]
  PIN x[17]
    DIRECTION INPUT ;
    USE SIGNAL ;
    PORT
      LAYER M4 ;
        RECT  0.054 8.832 0.138 8.856 ;
    END
  END x[17]
  PIN x[18]
    DIRECTION INPUT ;
    USE SIGNAL ;
    PORT
      LAYER M4 ;
        RECT  0.054 9.024 0.138 9.048 ;
    END
  END x[18]
  PIN x[19]
    DIRECTION INPUT ;
    USE SIGNAL ;
    PORT
      LAYER M4 ;
        RECT  0.054 9.264 0.138 9.288 ;
    END
  END x[19]
  PIN x[1]
    DIRECTION INPUT ;
    USE SIGNAL ;
    PORT
      LAYER M4 ;
        RECT  0.054 5.568 0.138 5.592 ;
    END
  END x[1]
  PIN x[20]
    DIRECTION INPUT ;
    USE SIGNAL ;
    PORT
      LAYER M4 ;
        RECT  0.054 9.456 0.138 9.48 ;
    END
  END x[20]
  PIN x[21]
    DIRECTION INPUT ;
    USE SIGNAL ;
    PORT
      LAYER M4 ;
        RECT  0.054 9.648 0.138 9.672 ;
    END
  END x[21]
  PIN x[22]
    DIRECTION INPUT ;
    USE SIGNAL ;
    PORT
      LAYER M4 ;
        RECT  0.054 9.84 0.138 9.864 ;
    END
  END x[22]
  PIN x[23]
    DIRECTION INPUT ;
    USE SIGNAL ;
    PORT
      LAYER M4 ;
        RECT  0.054 10.08 0.138 10.104 ;
    END
  END x[23]
  PIN x[24]
    DIRECTION INPUT ;
    USE SIGNAL ;
    PORT
      LAYER M4 ;
        RECT  0.054 10.272 0.138 10.296 ;
    END
  END x[24]
  PIN x[25]
    DIRECTION INPUT ;
    USE SIGNAL ;
    PORT
      LAYER M4 ;
        RECT  0.054 10.464 0.138 10.488 ;
    END
  END x[25]
  PIN x[26]
    DIRECTION INPUT ;
    USE SIGNAL ;
    PORT
      LAYER M4 ;
        RECT  0.054 10.656 0.138 10.68 ;
    END
  END x[26]
  PIN x[27]
    DIRECTION INPUT ;
    USE SIGNAL ;
    PORT
      LAYER M4 ;
        RECT  0.054 10.848 0.138 10.872 ;
    END
  END x[27]
  PIN x[28]
    DIRECTION INPUT ;
    USE SIGNAL ;
    PORT
      LAYER M4 ;
        RECT  0.054 11.088 0.138 11.112 ;
    END
  END x[28]
  PIN x[29]
    DIRECTION INPUT ;
    USE SIGNAL ;
    PORT
      LAYER M4 ;
        RECT  0.054 11.28 0.138 11.304 ;
    END
  END x[29]
  PIN x[2]
    DIRECTION INPUT ;
    USE SIGNAL ;
    PORT
      LAYER M4 ;
        RECT  0.054 5.808 0.138 5.832 ;
    END
  END x[2]
  PIN x[30]
    DIRECTION INPUT ;
    USE SIGNAL ;
    PORT
      LAYER M4 ;
        RECT  0.054 11.472 0.138 11.496 ;
    END
  END x[30]
  PIN x[31]
    DIRECTION INPUT ;
    USE SIGNAL ;
    PORT
      LAYER M4 ;
        RECT  0.054 11.664 0.138 11.688 ;
    END
  END x[31]
  PIN x[32]
    DIRECTION INPUT ;
    USE SIGNAL ;
    PORT
      LAYER M4 ;
        RECT  0.054 11.904 0.138 11.928 ;
    END
  END x[32]
  PIN x[33]
    DIRECTION INPUT ;
    USE SIGNAL ;
    PORT
      LAYER M4 ;
        RECT  0.054 12.096 0.138 12.12 ;
    END
  END x[33]
  PIN x[34]
    DIRECTION INPUT ;
    USE SIGNAL ;
    PORT
      LAYER M4 ;
        RECT  0.054 12.288 0.138 12.312 ;
    END
  END x[34]
  PIN x[35]
    DIRECTION INPUT ;
    USE SIGNAL ;
    PORT
      LAYER M4 ;
        RECT  0.054 12.48 0.138 12.504 ;
    END
  END x[35]
  PIN x[36]
    DIRECTION INPUT ;
    USE SIGNAL ;
    PORT
      LAYER M4 ;
        RECT  0.054 12.72 0.138 12.744 ;
    END
  END x[36]
  PIN x[37]
    DIRECTION INPUT ;
    USE SIGNAL ;
    PORT
      LAYER M4 ;
        RECT  0.054 12.912 0.138 12.936 ;
    END
  END x[37]
  PIN x[38]
    DIRECTION INPUT ;
    USE SIGNAL ;
    PORT
      LAYER M4 ;
        RECT  0.054 13.104 0.138 13.128 ;
    END
  END x[38]
  PIN x[39]
    DIRECTION INPUT ;
    USE SIGNAL ;
    PORT
      LAYER M4 ;
        RECT  0.054 13.296 0.138 13.32 ;
    END
  END x[39]
  PIN x[3]
    DIRECTION INPUT ;
    USE SIGNAL ;
    PORT
      LAYER M4 ;
        RECT  0.054 6 0.138 6.024 ;
    END
  END x[3]
  PIN x[40]
    DIRECTION INPUT ;
    USE SIGNAL ;
    PORT
      LAYER M4 ;
        RECT  0.054 13.488 0.138 13.512 ;
    END
  END x[40]
  PIN x[41]
    DIRECTION INPUT ;
    USE SIGNAL ;
    PORT
      LAYER M4 ;
        RECT  0.054 13.728 0.138 13.752 ;
    END
  END x[41]
  PIN x[42]
    DIRECTION INPUT ;
    USE SIGNAL ;
    PORT
      LAYER M4 ;
        RECT  0.054 13.92 0.138 13.944 ;
    END
  END x[42]
  PIN x[43]
    DIRECTION INPUT ;
    USE SIGNAL ;
    PORT
      LAYER M4 ;
        RECT  0.054 14.112 0.138 14.136 ;
    END
  END x[43]
  PIN x[44]
    DIRECTION INPUT ;
    USE SIGNAL ;
    PORT
      LAYER M4 ;
        RECT  0.054 14.304 0.138 14.328 ;
    END
  END x[44]
  PIN x[45]
    DIRECTION INPUT ;
    USE SIGNAL ;
    PORT
      LAYER M4 ;
        RECT  0.054 14.544 0.138 14.568 ;
    END
  END x[45]
  PIN x[46]
    DIRECTION INPUT ;
    USE SIGNAL ;
    PORT
      LAYER M4 ;
        RECT  0.054 14.736 0.138 14.76 ;
    END
  END x[46]
  PIN x[47]
    DIRECTION INPUT ;
    USE SIGNAL ;
    PORT
      LAYER M4 ;
        RECT  0.054 14.928 0.138 14.952 ;
    END
  END x[47]
  PIN x[48]
    DIRECTION INPUT ;
    USE SIGNAL ;
    PORT
      LAYER M4 ;
        RECT  0.054 15.12 0.138 15.144 ;
    END
  END x[48]
  PIN x[49]
    DIRECTION INPUT ;
    USE SIGNAL ;
    PORT
      LAYER M4 ;
        RECT  0.054 15.312 0.138 15.336 ;
    END
  END x[49]
  PIN x[4]
    DIRECTION INPUT ;
    USE SIGNAL ;
    PORT
      LAYER M4 ;
        RECT  0.054 6.192 0.138 6.216 ;
    END
  END x[4]
  PIN x[50]
    DIRECTION INPUT ;
    USE SIGNAL ;
    PORT
      LAYER M4 ;
        RECT  0.054 15.552 0.138 15.576 ;
    END
  END x[50]
  PIN x[51]
    DIRECTION INPUT ;
    USE SIGNAL ;
    PORT
      LAYER M4 ;
        RECT  0.054 15.744 0.138 15.768 ;
    END
  END x[51]
  PIN x[52]
    DIRECTION INPUT ;
    USE SIGNAL ;
    PORT
      LAYER M4 ;
        RECT  0.054 15.936 0.138 15.96 ;
    END
  END x[52]
  PIN x[53]
    DIRECTION INPUT ;
    USE SIGNAL ;
    PORT
      LAYER M4 ;
        RECT  0.054 16.128 0.138 16.152 ;
    END
  END x[53]
  PIN x[54]
    DIRECTION INPUT ;
    USE SIGNAL ;
    PORT
      LAYER M4 ;
        RECT  0.054 16.368 0.138 16.392 ;
    END
  END x[54]
  PIN x[55]
    DIRECTION INPUT ;
    USE SIGNAL ;
    PORT
      LAYER M4 ;
        RECT  0.054 16.56 0.138 16.584 ;
    END
  END x[55]
  PIN x[56]
    DIRECTION INPUT ;
    USE SIGNAL ;
    PORT
      LAYER M4 ;
        RECT  0.054 16.752 0.138 16.776 ;
    END
  END x[56]
  PIN x[57]
    DIRECTION INPUT ;
    USE SIGNAL ;
    PORT
      LAYER M4 ;
        RECT  0.054 16.944 0.138 16.968 ;
    END
  END x[57]
  PIN x[58]
    DIRECTION INPUT ;
    USE SIGNAL ;
    PORT
      LAYER M4 ;
        RECT  0.054 17.184 0.138 17.208 ;
    END
  END x[58]
  PIN x[59]
    DIRECTION INPUT ;
    USE SIGNAL ;
    PORT
      LAYER M4 ;
        RECT  0.054 17.376 0.138 17.4 ;
    END
  END x[59]
  PIN x[5]
    DIRECTION INPUT ;
    USE SIGNAL ;
    PORT
      LAYER M4 ;
        RECT  0.054 6.384 0.138 6.408 ;
    END
  END x[5]
  PIN x[60]
    DIRECTION INPUT ;
    USE SIGNAL ;
    PORT
      LAYER M4 ;
        RECT  0.054 17.568 0.138 17.592 ;
    END
  END x[60]
  PIN x[61]
    DIRECTION INPUT ;
    USE SIGNAL ;
    PORT
      LAYER M4 ;
        RECT  0.054 17.76 0.138 17.784 ;
    END
  END x[61]
  PIN x[62]
    DIRECTION INPUT ;
    USE SIGNAL ;
    PORT
      LAYER M4 ;
        RECT  0.054 17.952 0.138 17.976 ;
    END
  END x[62]
  PIN x[63]
    DIRECTION INPUT ;
    USE SIGNAL ;
    PORT
      LAYER M4 ;
        RECT  0.054 18.192 0.138 18.216 ;
    END
  END x[63]
  PIN x[64]
    DIRECTION INPUT ;
    USE SIGNAL ;
    PORT
      LAYER M4 ;
        RECT  0.054 18.384 0.138 18.408 ;
    END
  END x[64]
  PIN x[65]
    DIRECTION INPUT ;
    USE SIGNAL ;
    PORT
      LAYER M4 ;
        RECT  0.054 18.576 0.138 18.6 ;
    END
  END x[65]
  PIN x[66]
    DIRECTION INPUT ;
    USE SIGNAL ;
    PORT
      LAYER M4 ;
        RECT  0.054 18.768 0.138 18.792 ;
    END
  END x[66]
  PIN x[67]
    DIRECTION INPUT ;
    USE SIGNAL ;
    PORT
      LAYER M4 ;
        RECT  0.054 19.008 0.138 19.032 ;
    END
  END x[67]
  PIN x[68]
    DIRECTION INPUT ;
    USE SIGNAL ;
    PORT
      LAYER M4 ;
        RECT  0.054 19.2 0.138 19.224 ;
    END
  END x[68]
  PIN x[69]
    DIRECTION INPUT ;
    USE SIGNAL ;
    PORT
      LAYER M4 ;
        RECT  0.054 19.392 0.138 19.416 ;
    END
  END x[69]
  PIN x[6]
    DIRECTION INPUT ;
    USE SIGNAL ;
    PORT
      LAYER M4 ;
        RECT  0.054 6.624 0.138 6.648 ;
    END
  END x[6]
  PIN x[70]
    DIRECTION INPUT ;
    USE SIGNAL ;
    PORT
      LAYER M4 ;
        RECT  0.054 19.584 0.138 19.608 ;
    END
  END x[70]
  PIN x[71]
    DIRECTION INPUT ;
    USE SIGNAL ;
    PORT
      LAYER M4 ;
        RECT  0.054 19.824 0.138 19.848 ;
    END
  END x[71]
  PIN x[72]
    DIRECTION INPUT ;
    USE SIGNAL ;
    PORT
      LAYER M4 ;
        RECT  0.054 20.016 0.138 20.04 ;
    END
  END x[72]
  PIN x[73]
    DIRECTION INPUT ;
    USE SIGNAL ;
    PORT
      LAYER M4 ;
        RECT  0.054 20.208 0.138 20.232 ;
    END
  END x[73]
  PIN x[74]
    DIRECTION INPUT ;
    USE SIGNAL ;
    PORT
      LAYER M4 ;
        RECT  0.054 20.4 0.138 20.424 ;
    END
  END x[74]
  PIN x[75]
    DIRECTION INPUT ;
    USE SIGNAL ;
    PORT
      LAYER M4 ;
        RECT  0.054 20.592 0.138 20.616 ;
    END
  END x[75]
  PIN x[76]
    DIRECTION INPUT ;
    USE SIGNAL ;
    PORT
      LAYER M4 ;
        RECT  0.054 20.832 0.138 20.856 ;
    END
  END x[76]
  PIN x[77]
    DIRECTION INPUT ;
    USE SIGNAL ;
    PORT
      LAYER M4 ;
        RECT  0.054 21.024 0.138 21.048 ;
    END
  END x[77]
  PIN x[78]
    DIRECTION INPUT ;
    USE SIGNAL ;
    PORT
      LAYER M4 ;
        RECT  0.054 21.216 0.138 21.24 ;
    END
  END x[78]
  PIN x[79]
    DIRECTION INPUT ;
    USE SIGNAL ;
    PORT
      LAYER M4 ;
        RECT  0.054 21.408 0.138 21.432 ;
    END
  END x[79]
  PIN x[7]
    DIRECTION INPUT ;
    USE SIGNAL ;
    PORT
      LAYER M4 ;
        RECT  0.054 6.816 0.138 6.84 ;
    END
  END x[7]
  PIN x[80]
    DIRECTION INPUT ;
    USE SIGNAL ;
    PORT
      LAYER M4 ;
        RECT  0.054 21.648 0.138 21.672 ;
    END
  END x[80]
  PIN x[81]
    DIRECTION INPUT ;
    USE SIGNAL ;
    PORT
      LAYER M4 ;
        RECT  0.054 21.84 0.138 21.864 ;
    END
  END x[81]
  PIN x[82]
    DIRECTION INPUT ;
    USE SIGNAL ;
    PORT
      LAYER M4 ;
        RECT  0.054 22.032 0.138 22.056 ;
    END
  END x[82]
  PIN x[83]
    DIRECTION INPUT ;
    USE SIGNAL ;
    PORT
      LAYER M4 ;
        RECT  0.054 22.224 0.138 22.248 ;
    END
  END x[83]
  PIN x[84]
    DIRECTION INPUT ;
    USE SIGNAL ;
    PORT
      LAYER M4 ;
        RECT  0.054 22.464 0.138 22.488 ;
    END
  END x[84]
  PIN x[85]
    DIRECTION INPUT ;
    USE SIGNAL ;
    PORT
      LAYER M4 ;
        RECT  0.054 22.656 0.138 22.68 ;
    END
  END x[85]
  PIN x[86]
    DIRECTION INPUT ;
    USE SIGNAL ;
    PORT
      LAYER M4 ;
        RECT  0.054 22.848 0.138 22.872 ;
    END
  END x[86]
  PIN x[87]
    DIRECTION INPUT ;
    USE SIGNAL ;
    PORT
      LAYER M4 ;
        RECT  0.054 23.04 0.138 23.064 ;
    END
  END x[87]
  PIN x[88]
    DIRECTION INPUT ;
    USE SIGNAL ;
    PORT
      LAYER M4 ;
        RECT  0.054 23.232 0.138 23.256 ;
    END
  END x[88]
  PIN x[89]
    DIRECTION INPUT ;
    USE SIGNAL ;
    PORT
      LAYER M4 ;
        RECT  0.054 23.472 0.138 23.496 ;
    END
  END x[89]
  PIN x[8]
    DIRECTION INPUT ;
    USE SIGNAL ;
    PORT
      LAYER M4 ;
        RECT  0.054 7.008 0.138 7.032 ;
    END
  END x[8]
  PIN x[90]
    DIRECTION INPUT ;
    USE SIGNAL ;
    PORT
      LAYER M4 ;
        RECT  0.054 23.664 0.138 23.688 ;
    END
  END x[90]
  PIN x[91]
    DIRECTION INPUT ;
    USE SIGNAL ;
    PORT
      LAYER M4 ;
        RECT  0.054 23.856 0.138 23.88 ;
    END
  END x[91]
  PIN x[92]
    DIRECTION INPUT ;
    USE SIGNAL ;
    PORT
      LAYER M4 ;
        RECT  0.054 24.048 0.138 24.072 ;
    END
  END x[92]
  PIN x[93]
    DIRECTION INPUT ;
    USE SIGNAL ;
    PORT
      LAYER M4 ;
        RECT  0.054 24.288 0.138 24.312 ;
    END
  END x[93]
  PIN x[94]
    DIRECTION INPUT ;
    USE SIGNAL ;
    PORT
      LAYER M4 ;
        RECT  0.054 24.48 0.138 24.504 ;
    END
  END x[94]
  PIN x[95]
    DIRECTION INPUT ;
    USE SIGNAL ;
    PORT
      LAYER M4 ;
        RECT  0.054 24.672 0.138 24.696 ;
    END
  END x[95]
  PIN x[96]
    DIRECTION INPUT ;
    USE SIGNAL ;
    PORT
      LAYER M4 ;
        RECT  0.054 24.864 0.138 24.888 ;
    END
  END x[96]
  PIN x[97]
    DIRECTION INPUT ;
    USE SIGNAL ;
    PORT
      LAYER M4 ;
        RECT  0.054 25.056 0.138 25.08 ;
    END
  END x[97]
  PIN x[98]
    DIRECTION INPUT ;
    USE SIGNAL ;
    PORT
      LAYER M4 ;
        RECT  0.054 25.296 0.138 25.32 ;
    END
  END x[98]
  PIN x[99]
    DIRECTION INPUT ;
    USE SIGNAL ;
    PORT
      LAYER M4 ;
        RECT  0.054 25.488 0.138 25.512 ;
    END
  END x[99]
  PIN x[9]
    DIRECTION INPUT ;
    USE SIGNAL ;
    PORT
      LAYER M4 ;
        RECT  0.054 7.2 0.138 7.224 ;
    END
  END x[9]
  PIN VDD
    DIRECTION INOUT ;
    USE POWER ;
    PORT
      LAYER M5 ;
        RECT  10.692 2.151 10.812 62.649 ;
        RECT  7.992 2.151 8.112 62.649 ;
        RECT  5.292 2.151 5.412 62.649 ;
        RECT  2.592 2.151 2.712 62.649 ;
    END
  END VDD
  PIN VSS
    DIRECTION INOUT ;
    USE GROUND ;
    PORT
      LAYER M5 ;
        RECT  10.5 2.137 10.62 62.663 ;
        RECT  7.8 2.137 7.92 62.663 ;
        RECT  5.1 2.137 5.22 62.663 ;
        RECT  2.4 2.137 2.52 62.663 ;
    END
  END VSS
  # OT_OBS_CLOSED layer=M5 d_um=1.536 added=56
  OBS
    LAYER RVTN ;
     RECT  2.16 2.16 12.96 2.295 ;
     RECT  2.16 2.565 12.96 2.835 ;
     RECT  2.16 3.105 12.96 3.375 ;
     RECT  2.16 3.645 12.96 3.915 ;
     RECT  2.16 4.185 12.96 4.455 ;
     RECT  2.16 4.725 12.96 4.995 ;
     RECT  2.16 5.265 12.96 5.535 ;
     RECT  2.16 5.805 12.96 6.075 ;
     RECT  2.16 6.345 12.96 6.615 ;
     RECT  2.16 6.885 12.96 7.155 ;
     RECT  2.16 7.425 12.96 7.695 ;
     RECT  2.16 7.965 12.96 8.235 ;
     RECT  2.16 8.505 12.96 8.775 ;
     RECT  2.16 9.045 12.96 9.315 ;
     RECT  2.16 9.585 12.96 9.855 ;
     RECT  2.16 10.125 12.96 10.395 ;
     RECT  2.16 10.665 12.96 10.935 ;
     RECT  2.16 11.205 12.96 11.475 ;
     RECT  2.16 11.745 12.96 12.015 ;
     RECT  2.16 12.285 12.96 12.555 ;
     RECT  2.16 12.825 12.96 13.095 ;
     RECT  2.16 13.365 12.96 13.635 ;
     RECT  2.16 13.905 12.96 14.175 ;
     RECT  2.16 14.445 12.96 14.715 ;
     RECT  2.16 14.985 12.96 15.255 ;
     RECT  2.16 15.525 12.96 15.795 ;
     RECT  2.16 16.065 12.96 16.335 ;
     RECT  2.16 16.605 12.96 16.875 ;
     RECT  2.16 17.145 12.96 17.415 ;
     RECT  2.16 17.685 12.96 17.955 ;
     RECT  2.16 18.225 12.96 18.495 ;
     RECT  2.16 18.765 12.96 19.035 ;
     RECT  2.16 19.305 12.96 19.575 ;
     RECT  2.16 19.845 12.96 20.115 ;
     RECT  2.16 20.385 12.96 20.655 ;
     RECT  2.16 20.925 12.96 21.195 ;
     RECT  2.16 21.465 12.96 21.735 ;
     RECT  2.16 22.005 12.96 22.275 ;
     RECT  2.16 22.545 12.96 22.815 ;
     RECT  2.16 23.085 12.96 23.355 ;
     RECT  2.16 23.625 12.96 23.895 ;
     RECT  2.16 24.165 12.96 24.435 ;
     RECT  2.16 24.705 12.96 24.975 ;
     RECT  2.16 25.245 12.96 25.515 ;
     RECT  2.16 25.785 12.96 26.055 ;
     RECT  2.16 26.325 12.96 26.595 ;
     RECT  2.16 26.865 12.96 27.135 ;
     RECT  2.16 27.405 12.96 27.675 ;
     RECT  2.16 27.945 12.96 28.215 ;
     RECT  2.16 28.485 12.96 28.755 ;
     RECT  2.16 29.025 12.96 29.295 ;
     RECT  2.16 29.565 12.96 29.835 ;
     RECT  2.16 30.105 12.96 30.375 ;
     RECT  2.16 30.645 12.96 30.915 ;
     RECT  2.16 31.185 12.96 31.455 ;
     RECT  2.16 31.725 12.96 31.995 ;
     RECT  2.16 32.265 12.96 32.535 ;
     RECT  2.16 32.805 12.96 33.075 ;
     RECT  2.16 33.345 12.96 33.615 ;
     RECT  2.16 33.885 12.96 34.155 ;
     RECT  2.16 34.425 12.96 34.695 ;
     RECT  2.16 34.965 12.96 35.235 ;
     RECT  2.16 35.505 12.96 35.775 ;
     RECT  2.16 36.045 12.96 36.315 ;
     RECT  2.16 36.585 12.96 36.855 ;
     RECT  2.16 37.125 12.96 37.395 ;
     RECT  2.16 37.665 12.96 37.935 ;
     RECT  2.16 38.205 12.96 38.475 ;
     RECT  2.16 38.745 12.96 39.015 ;
     RECT  2.16 39.285 12.96 39.555 ;
     RECT  2.16 39.825 12.96 40.095 ;
     RECT  2.16 40.365 12.96 40.635 ;
     RECT  2.16 40.905 12.96 41.175 ;
     RECT  2.16 41.445 12.96 41.715 ;
     RECT  2.16 41.985 12.96 42.255 ;
     RECT  2.16 42.525 12.96 42.795 ;
     RECT  2.16 43.065 12.96 43.335 ;
     RECT  2.16 43.605 12.96 43.875 ;
     RECT  2.16 44.145 12.96 44.415 ;
     RECT  2.16 44.685 12.96 44.955 ;
     RECT  2.16 45.225 12.96 45.495 ;
     RECT  2.16 45.765 12.96 46.035 ;
     RECT  2.16 46.305 12.96 46.575 ;
     RECT  2.16 46.845 12.96 47.115 ;
     RECT  2.16 47.385 12.96 47.655 ;
     RECT  2.16 47.925 12.96 48.195 ;
     RECT  2.16 48.465 12.96 48.735 ;
     RECT  2.16 49.005 12.96 49.275 ;
     RECT  2.16 49.545 12.96 49.815 ;
     RECT  2.16 50.085 12.96 50.355 ;
     RECT  2.16 50.625 12.96 50.895 ;
     RECT  2.16 51.165 12.96 51.435 ;
     RECT  2.16 51.705 12.96 51.975 ;
     RECT  2.16 52.245 12.96 52.515 ;
     RECT  2.16 52.785 12.96 53.055 ;
     RECT  2.16 53.325 12.96 53.595 ;
     RECT  2.16 53.865 12.96 54.135 ;
     RECT  2.16 54.405 12.96 54.675 ;
     RECT  2.16 54.945 12.96 55.215 ;
     RECT  2.16 55.485 12.96 55.755 ;
     RECT  2.16 56.025 12.96 56.295 ;
     RECT  2.16 56.565 12.96 56.835 ;
     RECT  2.16 57.105 12.96 57.375 ;
     RECT  2.16 57.645 12.96 57.915 ;
     RECT  2.16 58.185 12.96 58.455 ;
     RECT  2.16 58.725 12.96 58.995 ;
     RECT  2.16 59.265 12.96 59.535 ;
     RECT  2.16 59.805 12.96 60.075 ;
     RECT  2.16 60.345 12.96 60.615 ;
     RECT  2.16 60.885 12.96 61.155 ;
     RECT  2.16 61.425 12.96 61.695 ;
     RECT  2.16 61.965 12.96 62.235 ;
     RECT  2.16 62.505 12.96 62.64 ;
    LAYER RVTP ;
     RECT  2.16 2.295 12.96 2.565 ;
     RECT  2.16 2.835 12.96 3.105 ;
     RECT  2.16 3.375 12.96 3.645 ;
     RECT  2.16 3.915 12.96 4.185 ;
     RECT  2.16 4.455 12.96 4.725 ;
     RECT  2.16 4.995 12.96 5.265 ;
     RECT  2.16 5.535 12.96 5.805 ;
     RECT  2.16 6.075 12.96 6.345 ;
     RECT  2.16 6.615 12.96 6.885 ;
     RECT  2.16 7.155 12.96 7.425 ;
     RECT  2.16 7.695 12.96 7.965 ;
     RECT  2.16 8.235 12.96 8.505 ;
     RECT  2.16 8.775 12.96 9.045 ;
     RECT  2.16 9.315 12.96 9.585 ;
     RECT  2.16 9.855 12.96 10.125 ;
     RECT  2.16 10.395 12.96 10.665 ;
     RECT  2.16 10.935 12.96 11.205 ;
     RECT  2.16 11.475 12.96 11.745 ;
     RECT  2.16 12.015 12.96 12.285 ;
     RECT  2.16 12.555 12.96 12.825 ;
     RECT  2.16 13.095 12.96 13.365 ;
     RECT  2.16 13.635 12.96 13.905 ;
     RECT  2.16 14.175 12.96 14.445 ;
     RECT  2.16 14.715 12.96 14.985 ;
     RECT  2.16 15.255 12.96 15.525 ;
     RECT  2.16 15.795 12.96 16.065 ;
     RECT  2.16 16.335 12.96 16.605 ;
     RECT  2.16 16.875 12.96 17.145 ;
     RECT  2.16 17.415 12.96 17.685 ;
     RECT  2.16 17.955 12.96 18.225 ;
     RECT  2.16 18.495 12.96 18.765 ;
     RECT  2.16 19.035 12.96 19.305 ;
     RECT  2.16 19.575 12.96 19.845 ;
     RECT  2.16 20.115 12.96 20.385 ;
     RECT  2.16 20.655 12.96 20.925 ;
     RECT  2.16 21.195 12.96 21.465 ;
     RECT  2.16 21.735 12.96 22.005 ;
     RECT  2.16 22.275 12.96 22.545 ;
     RECT  2.16 22.815 12.96 23.085 ;
     RECT  2.16 23.355 12.96 23.625 ;
     RECT  2.16 23.895 12.96 24.165 ;
     RECT  2.16 24.435 12.96 24.705 ;
     RECT  2.16 24.975 12.96 25.245 ;
     RECT  2.16 25.515 12.96 25.785 ;
     RECT  2.16 26.055 12.96 26.325 ;
     RECT  2.16 26.595 12.96 26.865 ;
     RECT  2.16 27.135 12.96 27.405 ;
     RECT  2.16 27.675 12.96 27.945 ;
     RECT  2.16 28.215 12.96 28.485 ;
     RECT  2.16 28.755 12.96 29.025 ;
     RECT  2.16 29.295 12.96 29.565 ;
     RECT  2.16 29.835 12.96 30.105 ;
     RECT  2.16 30.375 12.96 30.645 ;
     RECT  2.16 30.915 12.96 31.185 ;
     RECT  2.16 31.455 12.96 31.725 ;
     RECT  2.16 31.995 12.96 32.265 ;
     RECT  2.16 32.535 12.96 32.805 ;
     RECT  2.16 33.075 12.96 33.345 ;
     RECT  2.16 33.615 12.96 33.885 ;
     RECT  2.16 34.155 12.96 34.425 ;
     RECT  2.16 34.695 12.96 34.965 ;
     RECT  2.16 35.235 12.96 35.505 ;
     RECT  2.16 35.775 12.96 36.045 ;
     RECT  2.16 36.315 12.96 36.585 ;
     RECT  2.16 36.855 12.96 37.125 ;
     RECT  2.16 37.395 12.96 37.665 ;
     RECT  2.16 37.935 12.96 38.205 ;
     RECT  2.16 38.475 12.96 38.745 ;
     RECT  2.16 39.015 12.96 39.285 ;
     RECT  2.16 39.555 12.96 39.825 ;
     RECT  2.16 40.095 12.96 40.365 ;
     RECT  2.16 40.635 12.96 40.905 ;
     RECT  2.16 41.175 12.96 41.445 ;
     RECT  2.16 41.715 12.96 41.985 ;
     RECT  2.16 42.255 12.96 42.525 ;
     RECT  2.16 42.795 12.96 43.065 ;
     RECT  2.16 43.335 12.96 43.605 ;
     RECT  2.16 43.875 12.96 44.145 ;
     RECT  2.16 44.415 12.96 44.685 ;
     RECT  2.16 44.955 12.96 45.225 ;
     RECT  2.16 45.495 12.96 45.765 ;
     RECT  2.16 46.035 12.96 46.305 ;
     RECT  2.16 46.575 12.96 46.845 ;
     RECT  2.16 47.115 12.96 47.385 ;
     RECT  2.16 47.655 12.96 47.925 ;
     RECT  2.16 48.195 12.96 48.465 ;
     RECT  2.16 48.735 12.96 49.005 ;
     RECT  2.16 49.275 12.96 49.545 ;
     RECT  2.16 49.815 12.96 50.085 ;
     RECT  2.16 50.355 12.96 50.625 ;
     RECT  2.16 50.895 12.96 51.165 ;
     RECT  2.16 51.435 12.96 51.705 ;
     RECT  2.16 51.975 12.96 52.245 ;
     RECT  2.16 52.515 12.96 52.785 ;
     RECT  2.16 53.055 12.96 53.325 ;
     RECT  2.16 53.595 12.96 53.865 ;
     RECT  2.16 54.135 12.96 54.405 ;
     RECT  2.16 54.675 12.96 54.945 ;
     RECT  2.16 55.215 12.96 55.485 ;
     RECT  2.16 55.755 12.96 56.025 ;
     RECT  2.16 56.295 12.96 56.565 ;
     RECT  2.16 56.835 12.96 57.105 ;
     RECT  2.16 57.375 12.96 57.645 ;
     RECT  2.16 57.915 12.96 58.185 ;
     RECT  2.16 58.455 12.96 58.725 ;
     RECT  2.16 58.995 12.96 59.265 ;
     RECT  2.16 59.535 12.96 59.805 ;
     RECT  2.16 60.075 12.96 60.345 ;
     RECT  2.16 60.615 12.96 60.885 ;
     RECT  2.16 61.155 12.96 61.425 ;
     RECT  2.16 61.695 12.96 61.965 ;
     RECT  2.16 62.235 12.96 62.505 ;
    LAYER M1 ;
     RECT  2.16 2.151 12.96 62.649 ;
    LAYER M2 ;
     RECT  0.139 7.2 0.535 7.956 ;
     RECT  0.139 13.842 0.535 13.86 ;
     RECT  0.535 6.696 2.16 7.956 ;
     RECT  0.139 11.952 2.16 12.51 ;
     RECT  0.535 13.446 2.16 13.86 ;
     RECT  0.139 19.08 2.16 19.098 ;
     RECT  0.139 20.322 2.16 20.34 ;
     RECT  0.535 22.212 2.16 22.23 ;
     RECT  0.139 25.56 2.16 26.082 ;
     RECT  0.139 28.458 2.16 28.476 ;
     RECT  0.139 30.654 2.16 30.672 ;
     RECT  0.535 55.8 2.16 55.818 ;
     RECT  0.535 57.996 2.16 58.014 ;
     RECT  2.16 2.151 12.96 62.649 ;
     RECT  12.96 27.036 13.091 32.454 ;
     RECT  12.96 59.544 13.091 61.074 ;
     RECT  12.96 7.056 13.559 26.244 ;
     RECT  13.091 27.036 13.559 31.248 ;
     RECT  12.96 33.246 13.559 53.244 ;
     RECT  13.091 32.346 13.595 32.454 ;
     RECT  13.559 14.958 13.631 24.156 ;
     RECT  13.559 7.056 13.667 14.004 ;
     RECT  13.631 14.958 13.667 22.194 ;
     RECT  13.631 22.986 13.667 24.156 ;
     RECT  13.559 25.02 13.667 26.244 ;
     RECT  13.559 27.036 13.667 30.294 ;
     RECT  13.559 31.23 13.667 31.248 ;
     RECT  13.559 35.28 13.667 41.904 ;
     RECT  13.559 42.966 13.667 53.244 ;
     RECT  13.091 59.706 13.667 61.074 ;
     RECT  13.667 15.066 13.703 16.524 ;
     RECT  13.667 38.376 13.703 38.664 ;
     RECT  13.667 48.906 14.171 49.464 ;
     RECT  13.667 11.376 14.207 12.744 ;
     RECT  13.667 20.826 14.207 22.194 ;
     RECT  14.171 48.906 14.207 49.194 ;
     RECT  13.667 50.256 14.207 51.894 ;
     RECT  13.667 52.686 14.207 53.244 ;
     RECT  12.96 54.036 14.207 57.834 ;
     RECT  12.96 4.806 14.243 5.364 ;
     RECT  13.667 7.056 14.243 8.694 ;
     RECT  13.667 9.594 14.243 9.846 ;
     RECT  14.207 11.376 14.243 11.934 ;
     RECT  14.207 12.726 14.243 12.744 ;
     RECT  13.667 13.536 14.243 13.626 ;
     RECT  13.703 15.606 14.243 16.524 ;
     RECT  13.667 17.586 14.243 20.034 ;
     RECT  14.207 20.826 14.243 21.384 ;
     RECT  14.207 22.176 14.243 22.194 ;
     RECT  13.667 22.986 14.243 23.004 ;
     RECT  13.667 23.796 14.243 23.814 ;
     RECT  13.667 25.146 14.243 25.164 ;
     RECT  13.667 26.028 14.243 26.244 ;
     RECT  13.667 27.036 14.243 28.134 ;
     RECT  13.667 28.926 14.243 29.484 ;
     RECT  13.667 30.276 14.243 30.294 ;
     RECT  13.559 33.246 14.243 34.344 ;
     RECT  13.667 35.28 14.243 36.234 ;
     RECT  13.703 38.376 14.243 38.394 ;
     RECT  13.667 39.528 14.243 40.824 ;
     RECT  13.667 41.886 14.243 41.904 ;
     RECT  13.667 42.966 14.243 43.794 ;
     RECT  13.667 45.126 14.243 45.414 ;
     RECT  13.667 46.476 14.243 48.114 ;
     RECT  14.207 48.906 14.243 48.924 ;
     RECT  14.207 50.256 14.243 50.814 ;
     RECT  14.207 51.876 14.243 51.894 ;
     RECT  14.207 52.686 14.243 52.704 ;
     RECT  14.207 54.036 14.243 54.054 ;
     RECT  14.207 54.846 14.243 54.864 ;
     RECT  14.207 55.926 14.243 57.024 ;
     RECT  14.207 57.816 14.243 57.834 ;
     RECT  12.96 6.246 14.279 6.264 ;
     RECT  14.243 15.768 14.279 16.524 ;
     RECT  14.243 26.028 14.279 26.046 ;
     RECT  13.595 32.436 14.279 32.454 ;
     RECT  14.243 39.528 14.279 39.546 ;
     RECT  14.243 43.578 14.279 43.596 ;
     RECT  14.243 47.466 14.279 47.484 ;
     RECT  14.243 56.268 14.279 56.286 ;
     RECT  13.667 60.084 14.891 61.074 ;
     RECT  14.243 5.076 14.927 5.364 ;
     RECT  14.927 5.076 14.963 5.094 ;
     RECT  14.243 7.776 14.963 7.794 ;
     RECT  14.243 11.376 14.963 11.394 ;
     RECT  14.279 16.506 14.963 16.524 ;
     RECT  14.243 19.008 14.963 19.026 ;
     RECT  14.243 27.216 14.963 27.234 ;
     RECT  14.243 34.326 14.963 34.344 ;
     RECT  13.667 37.602 14.963 37.62 ;
     RECT  14.891 60.084 14.963 60.804 ;
     RECT  14.935 58.626 15.071 58.644 ;
     RECT  14.963 60.786 15.071 60.804 ;
    LAYER M3 ;
     RECT  2.415 2.143 2.505 2.413 ;
     RECT  5.115 2.143 5.205 2.413 ;
     RECT  7.815 2.143 7.905 2.413 ;
     RECT  10.515 2.143 10.605 2.413 ;
     RECT  14.22 4.801 14.238 4.891 ;
     RECT  12.276 4.765 12.294 5.035 ;
     RECT  13.68 4.891 14.238 5.071 ;
     RECT  10.515 2.413 10.797 5.197 ;
     RECT  9.792 5.197 11.394 5.341 ;
     RECT  12.276 5.035 12.654 5.341 ;
     RECT  2.415 2.413 2.697 5.419 ;
     RECT  13.68 5.071 14.958 5.453 ;
     RECT  2.304 5.419 2.697 5.563 ;
     RECT  9.792 5.341 12.654 5.611 ;
     RECT  2.304 5.563 2.754 5.737 ;
     RECT  9.792 5.611 12.69 5.737 ;
     RECT  7.815 2.413 8.097 5.881 ;
     RECT  8.82 5.809 8.838 5.881 ;
     RECT  13.68 5.453 14.922 5.933 ;
     RECT  6.912 5.881 6.93 6.151 ;
     RECT  7.815 5.881 8.838 6.151 ;
     RECT  6.912 6.151 8.838 6.221 ;
     RECT  13.68 5.933 14.274 6.221 ;
     RECT  9.648 5.737 12.69 6.269 ;
     RECT  5.115 2.413 5.397 6.277 ;
     RECT  6.912 6.221 7.002 6.277 ;
     RECT  5.115 6.277 5.67 6.313 ;
     RECT  6.408 6.277 7.002 6.313 ;
     RECT  9.648 6.269 11.754 6.341 ;
     RECT  12.564 6.269 12.69 6.421 ;
     RECT  9.648 6.341 11.106 6.539 ;
     RECT  12.564 6.421 12.834 6.539 ;
     RECT  7.815 6.221 8.838 6.571 ;
     RECT  9.648 6.539 10.998 6.571 ;
     RECT  12.564 6.539 12.618 6.611 ;
     RECT  2.304 5.737 3.366 6.691 ;
     RECT  4.284 6.619 4.302 6.691 ;
     RECT  14.256 6.221 14.274 6.749 ;
     RECT  7.815 6.571 10.998 6.809 ;
     RECT  12.564 6.611 12.582 6.809 ;
     RECT  0.54 6.691 0.558 7.037 ;
     RECT  5.115 6.313 7.002 7.099 ;
     RECT  7.815 6.809 8.838 7.099 ;
     RECT  9.684 6.809 10.998 7.115 ;
     RECT  5.115 7.099 8.838 7.151 ;
     RECT  9.792 7.115 10.998 7.501 ;
     RECT  11.736 7.321 11.754 7.501 ;
     RECT  9.792 7.501 11.754 7.663 ;
     RECT  14.22 6.955 14.238 7.663 ;
     RECT  9.792 7.663 12.33 7.735 ;
     RECT  13.644 7.663 14.238 7.757 ;
     RECT  14.22 7.757 14.238 7.771 ;
     RECT  9.792 7.735 12.618 7.897 ;
     RECT  2.304 6.691 4.302 7.933 ;
     RECT  5.115 7.151 7.002 7.933 ;
     RECT  2.304 7.933 7.002 7.961 ;
     RECT  7.815 7.151 8.838 7.997 ;
     RECT  0.144 7.195 0.162 8.045 ;
     RECT  14.22 7.771 14.958 8.045 ;
     RECT  7.815 7.997 8.19 8.155 ;
     RECT  9.684 7.897 12.618 8.195 ;
     RECT  7.2 8.155 8.19 8.231 ;
     RECT  14.22 8.045 14.238 8.699 ;
     RECT  2.304 7.961 6.462 8.941 ;
     RECT  9.756 8.195 12.618 8.977 ;
     RECT  2.304 8.941 6.858 9.041 ;
     RECT  7.815 8.231 8.19 9.049 ;
     RECT  9.684 8.977 12.618 9.085 ;
     RECT  7.815 9.049 8.838 9.101 ;
     RECT  9.684 9.085 12.654 9.239 ;
     RECT  7.815 9.101 8.514 9.259 ;
     RECT  2.304 9.041 6.462 9.311 ;
     RECT  7.2 9.259 8.514 9.311 ;
     RECT  13.644 8.743 13.662 9.347 ;
     RECT  14.22 9.589 14.238 9.869 ;
     RECT  7.56 9.311 8.514 9.925 ;
     RECT  9.684 9.239 12.618 9.959 ;
     RECT  7.56 9.925 8.874 10.057 ;
     RECT  7.38 10.057 8.874 10.093 ;
     RECT  9.684 9.959 12.546 10.093 ;
     RECT  2.304 9.311 4.302 10.165 ;
     RECT  5.115 9.311 6.462 10.165 ;
     RECT  2.304 10.165 6.57 10.315 ;
     RECT  7.38 10.093 12.546 10.315 ;
     RECT  13.644 10.123 13.662 10.588 ;
     RECT  2.304 10.315 12.546 10.705 ;
     RECT  2.304 10.705 12.582 10.859 ;
     RECT  13.608 10.588 13.662 10.931 ;
     RECT  2.304 10.859 12.546 11.129 ;
     RECT  13.644 10.931 13.662 11.309 ;
     RECT  9.792 11.129 12.546 11.399 ;
     RECT  14.94 11.371 14.958 11.453 ;
     RECT  2.304 11.129 9.018 11.933 ;
     RECT  14.184 11.659 14.238 11.939 ;
     RECT  2.34 11.933 9.018 12.055 ;
     RECT  9.792 11.399 12.402 12.055 ;
     RECT  14.184 11.939 14.202 12.181 ;
     RECT  2.34 12.055 12.402 12.451 ;
     RECT  2.34 12.451 12.618 12.551 ;
     RECT  13.644 12.181 14.202 12.712 ;
     RECT  0.144 11.947 0.162 12.749 ;
     RECT  13.644 12.712 14.238 12.749 ;
     RECT  2.34 12.551 12.582 12.757 ;
     RECT  2.304 12.757 12.582 12.893 ;
     RECT  2.304 12.893 11.43 13.325 ;
     RECT  2.304 13.325 6.93 13.483 ;
     RECT  13.644 12.749 13.662 13.531 ;
     RECT  2.268 13.483 6.93 13.559 ;
     RECT  7.776 13.325 11.43 13.595 ;
     RECT  2.268 13.559 6.534 13.667 ;
     RECT  7.815 13.595 11.43 13.675 ;
     RECT  12.168 12.893 12.582 13.675 ;
     RECT  0.54 13.441 0.558 13.757 ;
     RECT  13.644 13.531 14.238 13.805 ;
     RECT  7.815 13.675 12.654 14.009 ;
     RECT  13.644 13.805 13.662 14.045 ;
     RECT  9.684 14.009 12.654 14.215 ;
     RECT  0.144 13.837 0.162 14.333 ;
     RECT  2.34 13.667 6.534 14.341 ;
     RECT  2.34 14.341 6.57 14.347 ;
     RECT  7.815 14.009 8.838 14.347 ;
     RECT  9.684 14.215 12.762 14.369 ;
     RECT  13.536 14.299 13.554 14.44 ;
     RECT  2.34 14.347 8.838 14.485 ;
     RECT  13.5 14.44 13.554 14.573 ;
     RECT  13.644 14.827 13.662 14.981 ;
     RECT  13.68 15.061 13.698 15.101 ;
     RECT  2.304 14.485 8.838 15.115 ;
     RECT  2.268 15.115 8.838 15.215 ;
     RECT  9.792 14.369 12.438 15.295 ;
     RECT  9.684 15.295 12.438 15.565 ;
     RECT  2.304 15.215 8.838 15.601 ;
     RECT  9.684 15.565 12.582 15.601 ;
     RECT  2.304 15.601 12.582 15.719 ;
     RECT  2.304 15.719 8.838 15.869 ;
     RECT  14.22 15.355 14.274 15.989 ;
     RECT  9.612 15.719 12.582 16.105 ;
     RECT  9.612 16.105 12.618 16.645 ;
     RECT  14.94 16.501 14.958 16.685 ;
     RECT  6.192 15.869 8.838 16.771 ;
     RECT  9.612 16.645 12.654 16.771 ;
     RECT  6.192 16.771 12.654 16.907 ;
     RECT  2.304 15.869 5.397 16.915 ;
     RECT  6.192 16.907 8.838 16.915 ;
     RECT  13.644 16.123 13.662 17.069 ;
     RECT  9.684 16.907 12.654 17.221 ;
     RECT  9.684 17.221 12.726 17.339 ;
     RECT  9.684 17.339 12.654 17.879 ;
     RECT  14.22 17.179 14.238 17.947 ;
     RECT  2.304 16.915 8.838 18.031 ;
     RECT  9.684 17.879 12.366 18.031 ;
     RECT  13.644 17.947 14.238 18.419 ;
     RECT  2.304 18.031 12.366 18.455 ;
     RECT  2.415 18.455 12.366 18.697 ;
     RECT  14.22 18.419 14.238 19.003 ;
     RECT  14.22 19.003 14.958 19.04 ;
     RECT  2.415 18.697 12.474 19.075 ;
     RECT  2.415 19.075 12.618 19.195 ;
     RECT  0.144 19.075 0.162 19.421 ;
     RECT  14.22 19.04 14.238 19.507 ;
     RECT  2.34 19.195 12.618 19.543 ;
     RECT  2.34 19.543 12.654 19.579 ;
     RECT  2.304 19.579 12.654 20.011 ;
     RECT  13.644 19.507 14.238 20.039 ;
     RECT  2.268 20.011 12.69 20.147 ;
     RECT  13.644 20.039 13.662 20.381 ;
     RECT  2.34 20.147 12.69 20.587 ;
     RECT  2.34 20.587 13.086 20.759 ;
     RECT  0.144 20.317 0.162 21.053 ;
     RECT  2.34 20.759 12.654 21.119 ;
     RECT  2.34 21.119 12.618 21.211 ;
     RECT  14.22 20.821 14.238 21.355 ;
     RECT  2.304 21.211 12.618 21.643 ;
     RECT  14.184 21.355 14.238 21.643 ;
     RECT  2.268 21.643 12.618 21.695 ;
     RECT  0.54 22.207 0.558 22.253 ;
     RECT  2.304 21.695 12.618 22.279 ;
     RECT  13.644 21.643 14.238 22.411 ;
     RECT  2.304 22.279 12.654 22.469 ;
     RECT  13.608 22.411 14.238 23.009 ;
     RECT  2.304 22.469 12.582 23.153 ;
     RECT  13.608 23.009 13.662 23.227 ;
     RECT  13.572 23.227 13.662 23.755 ;
     RECT  13.572 23.755 14.238 23.819 ;
     RECT  2.304 23.153 12.546 23.899 ;
     RECT  13.572 23.819 13.662 23.995 ;
     RECT  2.304 23.899 12.618 24.359 ;
     RECT  13.536 23.995 13.662 24.737 ;
     RECT  13.572 24.737 13.662 24.763 ;
     RECT  13.572 24.763 14.238 25.079 ;
     RECT  13.608 25.079 14.238 25.241 ;
     RECT  2.304 24.359 12.474 25.285 ;
     RECT  13.644 25.241 14.238 25.579 ;
     RECT  2.304 25.285 12.618 25.591 ;
     RECT  2.304 25.591 12.654 25.789 ;
     RECT  2.304 25.789 12.726 25.979 ;
     RECT  13.644 25.579 14.274 26.159 ;
     RECT  0.144 25.555 0.162 26.621 ;
     RECT  14.184 26.159 14.274 26.635 ;
     RECT  2.304 25.979 12.69 26.797 ;
     RECT  2.268 26.797 12.69 27.163 ;
     RECT  2.268 27.163 13.086 27.203 ;
     RECT  14.184 26.635 14.958 27.239 ;
     RECT  14.184 27.239 14.238 27.643 ;
     RECT  13.572 27.643 14.238 27.779 ;
     RECT  2.268 27.203 12.582 28.147 ;
     RECT  2.268 28.147 12.618 28.175 ;
     RECT  0.144 28.453 0.162 28.541 ;
     RECT  2.304 28.175 12.618 29.065 ;
     RECT  2.304 29.065 12.654 29.219 ;
     RECT  13.644 27.779 14.238 29.755 ;
     RECT  2.304 29.219 12.474 30.065 ;
     RECT  2.415 30.065 12.474 30.283 ;
     RECT  13.572 29.755 14.238 30.283 ;
     RECT  2.415 30.283 14.238 30.299 ;
     RECT  0.144 30.331 0.162 30.797 ;
     RECT  2.415 30.299 13.554 30.955 ;
     RECT  2.304 30.955 13.554 31.051 ;
     RECT  2.304 31.051 13.662 31.253 ;
     RECT  2.304 31.253 13.59 31.289 ;
     RECT  7.815 31.289 13.59 32.099 ;
     RECT  2.304 31.289 6.966 32.155 ;
     RECT  7.815 32.099 8.838 32.155 ;
     RECT  9.612 32.099 13.59 32.261 ;
     RECT  13.572 32.261 13.59 32.369 ;
     RECT  9.612 32.261 12.654 32.459 ;
     RECT  14.22 32.431 14.274 32.669 ;
     RECT  9.684 32.459 12.654 33.163 ;
     RECT  9.684 33.163 13.086 33.269 ;
     RECT  2.304 32.155 8.838 33.421 ;
     RECT  9.72 33.269 13.086 33.421 ;
     RECT  9.72 33.421 13.122 33.485 ;
     RECT  2.304 33.421 8.946 33.575 ;
     RECT  14.22 32.669 14.238 33.809 ;
     RECT  13.644 33.979 13.662 34.151 ;
     RECT  9.72 33.485 12.834 34.195 ;
     RECT  9.612 34.195 12.834 34.219 ;
     RECT  14.94 34.321 14.958 34.493 ;
     RECT  2.304 33.575 8.874 34.501 ;
     RECT  9.612 34.219 13.554 34.501 ;
     RECT  2.304 34.501 13.554 34.637 ;
     RECT  9.612 34.637 13.554 34.763 ;
     RECT  13.5 34.763 13.554 35.021 ;
     RECT  9.612 34.763 12.654 35.429 ;
     RECT  2.304 34.637 8.874 36.121 ;
     RECT  9.612 35.429 12.474 36.121 ;
     RECT  2.304 36.121 12.474 36.355 ;
     RECT  13.644 35.275 14.238 36.365 ;
     RECT  2.304 36.355 12.654 36.553 ;
     RECT  13.644 36.365 13.662 36.553 ;
     RECT  2.304 36.553 13.662 36.605 ;
     RECT  13.644 36.605 13.662 37.387 ;
     RECT  13.608 37.387 13.662 37.427 ;
     RECT  14.94 37.597 14.958 37.661 ;
     RECT  2.304 36.605 12.474 37.705 ;
     RECT  2.304 37.705 12.654 37.859 ;
     RECT  2.304 37.859 12.474 37.895 ;
     RECT  13.644 37.427 13.662 38.201 ;
     RECT  13.68 38.371 14.238 38.429 ;
     RECT  2.304 37.895 6.21 38.677 ;
     RECT  6.948 37.895 12.474 38.677 ;
     RECT  13.68 38.429 13.698 38.717 ;
     RECT  2.304 38.677 12.474 38.785 ;
     RECT  2.304 38.785 12.582 38.939 ;
     RECT  2.304 38.939 8.838 38.975 ;
     RECT  9.684 38.939 12.582 39.091 ;
     RECT  6.588 38.975 8.838 39.341 ;
     RECT  13.644 38.923 13.662 39.389 ;
     RECT  9.684 39.091 12.654 39.515 ;
     RECT  13.68 39.451 14.274 39.551 ;
     RECT  2.304 38.975 5.85 39.757 ;
     RECT  6.588 39.341 8.766 39.757 ;
     RECT  2.304 39.757 8.766 39.883 ;
     RECT  13.68 39.551 14.238 40.013 ;
     RECT  2.268 39.883 8.766 40.055 ;
     RECT  9.828 39.515 12.654 40.297 ;
     RECT  2.304 40.055 8.766 40.369 ;
     RECT  2.304 40.369 8.838 40.445 ;
     RECT  14.184 40.013 14.238 40.541 ;
     RECT  2.304 40.445 8.766 40.595 ;
     RECT  14.22 40.541 14.238 40.829 ;
     RECT  9.576 40.297 12.654 41.035 ;
     RECT  2.415 40.595 8.766 41.251 ;
     RECT  9.576 41.035 13.086 41.251 ;
     RECT  2.415 41.251 13.086 41.275 ;
     RECT  2.415 41.275 13.662 41.323 ;
     RECT  2.304 41.323 13.662 41.441 ;
     RECT  9.684 41.441 13.662 41.549 ;
     RECT  13.536 41.549 13.662 41.803 ;
     RECT  13.536 41.803 14.238 41.909 ;
     RECT  9.684 41.549 12.654 42.331 ;
     RECT  13.536 41.909 13.662 42.331 ;
     RECT  2.304 41.441 8.766 42.379 ;
     RECT  2.304 42.379 8.874 42.449 ;
     RECT  9.684 42.331 12.762 42.449 ;
     RECT  9.684 42.449 12.654 42.457 ;
     RECT  13.5 42.331 13.662 42.557 ;
     RECT  9.648 42.457 12.654 42.755 ;
     RECT  13.608 42.557 13.662 42.859 ;
     RECT  9.684 42.755 12.654 43.133 ;
     RECT  13.608 42.859 14.238 43.259 ;
     RECT  2.304 42.449 8.766 43.387 ;
     RECT  13.644 43.259 14.238 43.573 ;
     RECT  9.684 43.133 12.546 44.221 ;
     RECT  9.648 44.221 12.546 44.419 ;
     RECT  13.644 43.573 14.274 44.477 ;
     RECT  9.648 44.419 12.582 44.609 ;
     RECT  2.304 43.387 8.838 44.645 ;
     RECT  2.304 44.645 8.766 44.779 ;
     RECT  2.268 44.779 8.766 44.915 ;
     RECT  9.648 44.609 12.402 44.915 ;
     RECT  13.644 44.477 14.238 45.419 ;
     RECT  9.684 44.915 12.402 45.535 ;
     RECT  2.304 44.915 8.766 45.769 ;
     RECT  9.684 45.535 12.654 45.769 ;
     RECT  2.304 45.769 12.654 45.959 ;
     RECT  2.304 45.959 12.366 46.229 ;
     RECT  13.644 45.419 13.662 46.267 ;
     RECT  2.304 46.229 12.258 46.373 ;
     RECT  2.304 46.373 8.874 46.685 ;
     RECT  13.644 46.267 14.238 46.795 ;
     RECT  9.612 46.373 12.258 47.155 ;
     RECT  9.612 47.155 12.726 47.323 ;
     RECT  13.608 46.795 14.238 47.323 ;
     RECT  2.304 46.685 8.766 47.425 ;
     RECT  9.612 47.323 14.238 47.425 ;
     RECT  2.304 47.425 14.238 47.461 ;
     RECT  2.304 47.461 14.274 47.579 ;
     RECT  9.684 47.579 12.726 47.849 ;
     RECT  13.644 47.579 14.274 47.885 ;
     RECT  13.644 47.885 14.238 48.191 ;
     RECT  2.304 47.579 8.874 48.389 ;
     RECT  9.72 47.849 12.618 48.389 ;
     RECT  9.72 48.389 12.474 48.775 ;
     RECT  14.148 48.191 14.238 48.929 ;
     RECT  6.948 48.389 8.874 48.973 ;
     RECT  9.612 48.775 12.474 48.973 ;
     RECT  6.948 48.973 12.474 49.037 ;
     RECT  14.148 48.929 14.202 49.147 ;
     RECT  7.815 49.037 12.474 49.199 ;
     RECT  13.644 49.147 14.202 49.199 ;
     RECT  2.304 48.389 6.21 49.315 ;
     RECT  6.948 49.037 6.966 49.315 ;
     RECT  2.304 49.315 6.966 49.469 ;
     RECT  9.684 49.199 12.474 49.477 ;
     RECT  13.644 49.199 14.166 49.675 ;
     RECT  6.948 49.469 6.966 49.963 ;
     RECT  7.815 49.199 8.874 49.963 ;
     RECT  13.608 49.675 14.166 49.963 ;
     RECT  2.304 49.469 6.21 50.009 ;
     RECT  6.948 49.963 8.874 50.009 ;
     RECT  9.684 49.477 12.582 50.081 ;
     RECT  2.304 50.009 4.338 50.117 ;
     RECT  7.815 50.009 8.874 50.125 ;
     RECT  13.608 49.963 14.238 50.203 ;
     RECT  7.815 50.125 9.054 50.279 ;
     RECT  5.115 50.009 6.21 50.395 ;
     RECT  6.948 50.009 6.966 50.395 ;
     RECT  9.792 50.081 12.582 50.395 ;
     RECT  9.792 50.395 12.618 50.549 ;
     RECT  5.115 50.395 6.966 50.731 ;
     RECT  9.792 50.549 12.474 50.899 ;
     RECT  5.004 50.731 6.966 51.061 ;
     RECT  7.815 50.279 8.838 51.061 ;
     RECT  2.304 50.117 4.266 51.205 ;
     RECT  5.004 51.061 8.838 51.205 ;
     RECT  2.304 51.205 8.838 51.245 ;
     RECT  5.115 51.245 8.838 51.269 ;
     RECT  13.536 50.203 14.238 51.269 ;
     RECT  0.144 51.163 0.162 51.293 ;
     RECT  2.304 51.245 4.194 51.431 ;
     RECT  2.304 51.431 3.978 51.629 ;
     RECT  9.684 50.899 12.474 51.781 ;
     RECT  5.115 51.269 6.966 52.015 ;
     RECT  9.684 51.781 12.654 52.027 ;
     RECT  4.716 52.015 6.966 52.123 ;
     RECT  7.815 51.269 8.838 52.123 ;
     RECT  9.684 52.027 12.69 52.169 ;
     RECT  9.756 52.169 12.69 52.285 ;
     RECT  13.572 51.269 14.238 52.349 ;
     RECT  9.756 52.285 12.726 52.439 ;
     RECT  13.644 52.349 14.238 52.709 ;
     RECT  2.304 51.629 3.942 52.861 ;
     RECT  4.716 52.123 8.838 52.861 ;
     RECT  2.268 52.861 9.018 52.925 ;
     RECT  2.304 52.925 9.018 52.979 ;
     RECT  2.304 52.979 8.838 53.051 ;
     RECT  9.756 52.439 12.618 53.095 ;
     RECT  9.684 53.095 12.618 53.249 ;
     RECT  9.756 53.249 12.618 53.519 ;
     RECT  13.644 52.709 14.202 53.611 ;
     RECT  2.304 53.051 8.766 54.091 ;
     RECT  9.756 53.519 12.474 54.091 ;
     RECT  13.644 53.611 14.238 54.139 ;
     RECT  2.304 54.091 12.474 54.445 ;
     RECT  2.304 54.445 12.582 54.743 ;
     RECT  2.304 54.743 8.838 54.985 ;
     RECT  9.576 54.743 12.582 54.985 ;
     RECT  2.268 54.985 8.838 54.989 ;
     RECT  2.268 54.989 8.766 55.133 ;
     RECT  2.304 55.133 8.766 55.409 ;
     RECT  9.576 54.985 12.618 55.435 ;
     RECT  13.536 54.139 14.238 55.435 ;
     RECT  9.576 55.435 14.238 55.589 ;
     RECT  9.576 55.589 13.086 55.751 ;
     RECT  14.184 55.589 14.238 55.757 ;
     RECT  14.22 55.757 14.238 55.948 ;
     RECT  0.54 55.795 0.558 55.949 ;
     RECT  9.576 55.751 12.474 56.057 ;
     RECT  9.756 56.057 12.474 56.129 ;
     RECT  4.5 55.409 8.766 56.219 ;
     RECT  12.456 56.129 12.474 56.219 ;
     RECT  14.22 55.948 14.274 56.291 ;
     RECT  14.22 56.291 14.238 56.488 ;
     RECT  4.68 56.219 8.766 56.867 ;
     RECT  9.756 56.129 11.646 56.875 ;
     RECT  6.768 56.867 8.766 57.001 ;
     RECT  14.184 56.488 14.238 57.019 ;
     RECT  13.644 57.019 14.238 57.101 ;
     RECT  9.756 56.875 11.826 57.145 ;
     RECT  4.68 56.867 5.706 57.181 ;
     RECT  2.304 55.409 3.258 57.451 ;
     RECT  6.768 57.001 9.018 57.569 ;
     RECT  2.304 57.451 3.33 57.577 ;
     RECT  4.32 57.181 5.706 57.577 ;
     RECT  7.2 57.569 9.018 57.577 ;
     RECT  9.756 57.145 12.546 57.577 ;
     RECT  7.2 57.577 12.546 57.787 ;
     RECT  14.184 57.101 14.238 57.839 ;
     RECT  7.2 57.787 13.086 57.875 ;
     RECT  7.2 57.875 12.222 58.019 ;
     RECT  13.068 57.875 13.086 58.075 ;
     RECT  9.792 58.019 12.222 58.109 ;
     RECT  9.972 58.109 12.222 58.157 ;
     RECT  2.304 57.577 5.706 58.189 ;
     RECT  6.444 57.955 6.462 58.189 ;
     RECT  0.54 57.991 0.558 58.205 ;
     RECT  2.304 58.189 6.462 58.351 ;
     RECT  7.2 58.019 9.054 58.351 ;
     RECT  10.116 58.157 12.222 58.379 ;
     RECT  2.304 58.351 9.054 58.451 ;
     RECT  12.168 58.379 12.222 58.621 ;
     RECT  13.068 58.075 13.662 58.621 ;
     RECT  14.94 58.603 14.958 58.621 ;
     RECT  5.004 58.451 9.054 58.649 ;
     RECT  2.304 58.451 4.158 58.721 ;
     RECT  5.115 58.649 9.054 58.835 ;
     RECT  7.272 58.835 9.054 58.955 ;
     RECT  5.115 58.835 6.498 59.063 ;
     RECT  7.776 58.955 9.054 59.071 ;
     RECT  7.776 59.071 9.378 59.099 ;
     RECT  14.94 58.621 15.066 59.131 ;
     RECT  10.44 58.379 11.358 59.161 ;
     RECT  12.168 58.621 13.662 59.161 ;
     RECT  7.815 59.099 9.378 59.189 ;
     RECT  10.44 59.161 13.662 59.275 ;
     RECT  5.115 59.063 6.282 59.297 ;
     RECT  5.115 59.297 6.21 59.369 ;
     RECT  2.304 58.721 4.086 59.371 ;
     RECT  14.904 59.131 15.066 59.371 ;
     RECT  2.268 59.371 4.086 59.459 ;
     RECT  5.115 59.369 5.814 59.467 ;
     RECT  2.304 59.459 4.086 59.495 ;
     RECT  4.824 59.467 5.814 59.531 ;
     RECT  5.004 59.531 5.814 59.567 ;
     RECT  9.828 59.275 13.662 59.567 ;
     RECT  2.304 59.495 3.438 59.729 ;
     RECT  9.828 59.567 12.618 59.729 ;
     RECT  13.392 59.567 13.662 59.729 ;
     RECT  2.304 59.729 3.15 59.765 ;
     RECT  10.44 59.729 12.618 59.765 ;
     RECT  10.44 59.765 12.582 59.801 ;
     RECT  2.34 59.765 2.697 59.837 ;
     RECT  5.004 59.567 5.742 59.999 ;
     RECT  4.248 59.611 4.266 60.035 ;
     RECT  5.115 59.999 5.742 60.035 ;
     RECT  10.515 59.801 12.582 60.035 ;
     RECT  13.392 59.729 13.41 60.269 ;
     RECT  11.808 60.035 12.582 60.305 ;
     RECT  12.06 60.305 12.582 60.575 ;
     RECT  14.868 59.371 15.066 60.809 ;
     RECT  12.348 60.575 12.582 60.845 ;
     RECT  14.868 60.809 14.886 61.079 ;
     RECT  12.348 60.845 12.366 61.115 ;
     RECT  2.415 59.837 2.697 62.387 ;
     RECT  5.115 60.035 5.397 62.387 ;
     RECT  7.815 59.189 8.097 62.387 ;
     RECT  10.515 60.035 10.797 62.387 ;
     RECT  2.415 62.387 2.505 62.657 ;
     RECT  5.115 62.387 5.205 62.657 ;
     RECT  7.815 62.387 7.905 62.657 ;
     RECT  10.515 62.387 10.605 62.657 ;
    LAYER M4 ;
     RECT  0.085 1.392 0.108 1.416 ;
     RECT  0.085 30.24 0.108 30.264 ;
     RECT  0.108 5.424 2.408 59.4 ;
     RECT  2.408 2.148 2.512 62.652 ;
     RECT  2.512 2.418 2.704 62.382 ;
     RECT  2.704 5.568 2.765 5.592 ;
     RECT  2.704 15.312 2.765 15.576 ;
     RECT  2.704 27.12 2.765 27.144 ;
     RECT  2.704 31.776 2.765 32.616 ;
     RECT  2.704 34.8 2.765 35.448 ;
     RECT  2.704 49.008 2.765 54.744 ;
     RECT  2.704 37.632 2.801 38.52 ;
     RECT  2.704 41.712 2.801 42.504 ;
     RECT  2.704 45.984 2.801 47.352 ;
     RECT  2.765 49.008 2.801 54.36 ;
     RECT  2.704 7.2 2.837 7.224 ;
     RECT  2.704 9.12 2.837 10.68 ;
     RECT  2.704 13.872 2.837 14.136 ;
     RECT  2.704 23.856 2.837 23.88 ;
     RECT  2.765 31.776 2.837 32.232 ;
     RECT  2.704 40.08 2.837 40.344 ;
     RECT  2.704 43.536 2.837 44.472 ;
     RECT  2.801 50.064 2.837 54.36 ;
     RECT  2.704 19.584 2.873 19.608 ;
     RECT  2.704 25.488 2.873 25.512 ;
     RECT  2.765 34.8 2.873 35.256 ;
     RECT  2.837 40.32 3.017 40.344 ;
     RECT  2.837 50.064 3.017 54.168 ;
     RECT  2.704 55.728 3.017 56.376 ;
     RECT  3.017 55.728 3.125 55.752 ;
     RECT  2.704 17.088 3.161 17.112 ;
     RECT  2.837 13.872 3.197 13.896 ;
     RECT  2.704 29.568 3.305 30.408 ;
     RECT  2.837 10.656 3.341 10.68 ;
     RECT  2.837 44.448 3.385 44.472 ;
     RECT  3.017 51.12 3.457 54.168 ;
     RECT  2.873 34.8 3.685 34.824 ;
     RECT  3.685 34.512 3.709 34.824 ;
     RECT  2.801 37.632 3.731 37.656 ;
     RECT  2.801 49.008 3.769 49.032 ;
     RECT  2.801 46.752 3.877 47.352 ;
     RECT  3.769 49.008 3.877 49.608 ;
     RECT  3.305 30.384 3.905 30.408 ;
     RECT  2.837 31.776 3.905 31.8 ;
     RECT  2.765 15.312 3.913 15.336 ;
     RECT  3.905 30.384 3.925 31.8 ;
     RECT  3.877 46.32 3.925 47.352 ;
     RECT  3.877 48.432 3.925 49.608 ;
     RECT  2.837 9.12 3.971 9.144 ;
     RECT  3.925 46.32 3.971 49.608 ;
     RECT  3.457 51.12 3.971 54.12 ;
     RECT  3.925 30.384 3.989 32.472 ;
     RECT  3.913 15.312 3.997 15.432 ;
     RECT  3.913 35.904 3.997 35.928 ;
     RECT  4.201 10.848 4.501 10.872 ;
     RECT  3.997 15.312 4.633 15.336 ;
     RECT  4.748 57.408 4.789 57.432 ;
     RECT  2.704 58.416 4.789 58.44 ;
     RECT  3.925 13.44 4.885 13.464 ;
     RECT  3.709 34.512 4.921 34.536 ;
     RECT  4.501 49.776 4.933 49.8 ;
     RECT  4.933 49.584 4.949 49.8 ;
     RECT  3.971 51.12 4.949 51.336 ;
     RECT  4.885 13.104 4.981 13.464 ;
     RECT  4.949 49.584 4.981 51.336 ;
     RECT  3.925 7.92 5.108 7.944 ;
     RECT  4.501 10.08 5.108 10.872 ;
     RECT  4.981 12.48 5.108 13.464 ;
     RECT  4.633 14.832 5.108 15.336 ;
     RECT  3.925 21.408 5.108 21.432 ;
     RECT  4.981 28.416 5.108 28.44 ;
     RECT  3.989 30.384 5.108 30.6 ;
     RECT  3.989 31.776 5.108 32.472 ;
     RECT  4.921 34.224 5.108 34.536 ;
     RECT  2.801 42.48 5.108 42.504 ;
     RECT  3.925 45.216 5.108 45.24 ;
     RECT  3.971 46.32 5.108 46.536 ;
     RECT  3.971 47.664 5.108 48.456 ;
     RECT  4.981 49.488 5.108 51.336 ;
     RECT  3.971 52.752 5.108 54.12 ;
     RECT  4.789 55.776 5.108 55.8 ;
     RECT  4.789 57.408 5.108 59.496 ;
     RECT  5.108 2.148 5.212 62.652 ;
     RECT  5.212 2.418 5.404 62.382 ;
     RECT  5.404 30.384 5.501 31.8 ;
     RECT  5.404 47.664 5.681 54.12 ;
     RECT  5.404 55.776 5.681 55.8 ;
     RECT  5.404 58.128 5.681 59.064 ;
     RECT  5.501 30.384 5.689 31.368 ;
     RECT  5.404 7.392 5.699 8.472 ;
     RECT  5.404 9.552 5.699 11.496 ;
     RECT  5.404 12.48 5.699 12.6 ;
     RECT  5.404 13.68 5.699 13.704 ;
     RECT  5.404 15.84 5.699 15.864 ;
     RECT  5.404 16.944 5.699 16.968 ;
     RECT  5.404 18 5.699 18.84 ;
     RECT  5.404 20.544 5.699 22.008 ;
     RECT  5.404 22.992 5.699 23.016 ;
     RECT  5.404 25.152 5.699 25.176 ;
     RECT  5.404 26.256 5.699 27.192 ;
     RECT  5.404 37.584 5.699 37.608 ;
     RECT  5.404 38.688 5.699 38.712 ;
     RECT  5.404 39.792 5.699 39.816 ;
     RECT  5.404 40.944 5.699 40.968 ;
     RECT  5.404 41.952 5.699 42.984 ;
     RECT  5.404 44.064 5.699 44.088 ;
     RECT  5.404 45.12 5.699 45.24 ;
     RECT  5.681 47.664 5.699 50.424 ;
     RECT  5.681 51.456 5.699 54.12 ;
     RECT  5.699 18.816 5.725 18.84 ;
     RECT  5.699 12.48 5.789 12.504 ;
     RECT  5.699 10.08 5.825 10.632 ;
     RECT  5.404 28.416 5.825 28.44 ;
     RECT  5.689 30.384 5.825 30.6 ;
     RECT  5.404 46.224 5.825 46.536 ;
     RECT  5.699 47.664 5.825 49.512 ;
     RECT  5.699 52.368 5.897 54.12 ;
     RECT  5.681 58.128 6.473 58.824 ;
     RECT  5.699 45.216 6.541 45.24 ;
     RECT  5.825 46.224 6.541 46.344 ;
     RECT  6.473 58.8 6.653 58.824 ;
     RECT  5.825 47.664 6.901 48.936 ;
     RECT  5.699 7.92 6.973 7.944 ;
     RECT  5.699 42.48 6.973 42.504 ;
     RECT  6.973 7.44 7.148 7.944 ;
     RECT  5.825 10.08 7.148 10.104 ;
     RECT  5.699 20.544 7.148 21.432 ;
     RECT  5.404 24.096 7.148 24.12 ;
     RECT  5.699 27.168 7.148 27.192 ;
     RECT  7.117 37.584 7.148 37.608 ;
     RECT  6.541 45.216 7.148 46.344 ;
     RECT  6.901 47.328 7.176 48.936 ;
     RECT  7.148 7.104 7.189 8.184 ;
     RECT  7.148 20.4 7.189 21.432 ;
     RECT  7.148 23.904 7.189 24.12 ;
     RECT  7.148 27.072 7.189 27.192 ;
     RECT  5.825 30.384 7.189 30.408 ;
     RECT  7.148 37.584 7.189 38.424 ;
     RECT  6.973 41.616 7.189 42.504 ;
     RECT  7.148 44.976 7.189 46.344 ;
     RECT  7.176 47.328 7.189 49.032 ;
     RECT  7.189 30.144 7.196 30.408 ;
     RECT  7.189 44.976 7.196 49.032 ;
     RECT  5.897 52.368 7.196 53.592 ;
     RECT  7.189 55.248 7.196 55.272 ;
     RECT  7.196 32.16 7.237 32.184 ;
     RECT  7.189 33.264 7.237 33.288 ;
     RECT  7.189 51.12 7.333 51.144 ;
     RECT  7.196 52.128 7.333 55.272 ;
     RECT  7.189 6.192 7.381 8.184 ;
     RECT  7.189 37.536 7.381 38.424 ;
     RECT  7.148 39.744 7.381 40.584 ;
     RECT  7.148 43.872 7.381 43.896 ;
     RECT  7.196 44.976 7.381 49.992 ;
     RECT  7.189 23.904 7.621 25.08 ;
     RECT  7.381 5.568 7.669 8.184 ;
     RECT  7.148 9.264 7.669 10.344 ;
     RECT  7.189 20.4 7.669 21.672 ;
     RECT  7.621 23.328 7.669 25.08 ;
     RECT  7.669 5.568 7.808 10.344 ;
     RECT  7.181 13.152 7.808 13.176 ;
     RECT  7.148 14.352 7.808 14.376 ;
     RECT  7.669 19.872 7.808 25.08 ;
     RECT  7.189 26.16 7.808 27.192 ;
     RECT  7.148 28.176 7.808 28.2 ;
     RECT  7.196 30.144 7.808 31.08 ;
     RECT  7.237 32.16 7.808 33.288 ;
     RECT  7.196 34.32 7.808 34.344 ;
     RECT  7.148 36.096 7.808 36.12 ;
     RECT  7.381 37.536 7.808 40.584 ;
     RECT  7.189 41.616 7.808 42.792 ;
     RECT  7.381 43.872 7.808 49.992 ;
     RECT  7.333 51.12 7.808 55.272 ;
     RECT  7.189 57.408 7.808 57.528 ;
     RECT  7.808 2.148 7.912 62.652 ;
     RECT  7.912 2.418 8.104 62.382 ;
     RECT  8.104 57.408 8.165 57.576 ;
     RECT  8.104 22.8 8.201 22.824 ;
     RECT  8.104 45.552 8.273 46.776 ;
     RECT  8.104 13.296 8.849 14.856 ;
     RECT  8.104 31.92 8.849 33.048 ;
     RECT  8.104 7.968 8.867 7.992 ;
     RECT  8.849 13.776 8.867 14.856 ;
     RECT  8.104 18.816 8.867 21.72 ;
     RECT  8.104 47.856 8.867 51.768 ;
     RECT  8.104 54.096 8.867 54.984 ;
     RECT  8.867 47.856 8.885 48.84 ;
     RECT  8.104 8.976 8.893 10.872 ;
     RECT  8.867 14.832 8.893 14.856 ;
     RECT  8.867 18.816 8.893 21.432 ;
     RECT  8.104 30.144 8.893 30.84 ;
     RECT  8.867 49.92 8.893 51.768 ;
     RECT  8.893 8.976 8.908 10.632 ;
     RECT  8.885 48.24 8.908 48.84 ;
     RECT  8.893 49.92 8.908 49.944 ;
     RECT  8.104 36.48 8.915 39.336 ;
     RECT  8.104 40.416 8.915 42.408 ;
     RECT  8.104 43.392 8.915 44.376 ;
     RECT  8.893 30.144 8.928 30.168 ;
     RECT  8.849 33.024 8.963 33.048 ;
     RECT  8.915 38.736 8.963 39.24 ;
     RECT  8.908 48.24 8.963 48.264 ;
     RECT  8.104 34.608 9.137 34.632 ;
     RECT  8.104 5.568 9.685 5.592 ;
     RECT  9.349 6.576 9.685 6.6 ;
     RECT  8.908 8.976 9.685 9 ;
     RECT  8.915 44.352 9.781 44.376 ;
     RECT  8.273 45.552 9.781 45.576 ;
     RECT  8.165 57.552 9.829 57.576 ;
     RECT  9.709 22.752 9.853 22.776 ;
     RECT  9.685 8.544 9.889 9 ;
     RECT  8.908 10.608 9.889 10.632 ;
     RECT  8.963 39.216 10.028 39.24 ;
     RECT  8.893 51.216 10.033 51.768 ;
     RECT  8.915 36.48 10.141 37.608 ;
     RECT  9.745 34.8 10.213 34.824 ;
     RECT  10.141 35.904 10.213 37.608 ;
     RECT  8.273 46.656 10.213 46.776 ;
     RECT  8.893 21.408 10.249 21.432 ;
     RECT  10.127 30.528 10.261 30.552 ;
     RECT  10.177 16.896 10.309 17.064 ;
     RECT  9.781 44.352 10.316 45.576 ;
     RECT  8.915 42 10.349 42.024 ;
     RECT  8.893 18.816 10.357 20.136 ;
     RECT  10.249 21.312 10.357 21.432 ;
     RECT  9.853 22.752 10.357 23.4 ;
     RECT  10.213 46.656 10.357 47.736 ;
     RECT  10.033 51.024 10.357 51.768 ;
     RECT  8.867 54.096 10.357 54.12 ;
     RECT  9.685 2.88 10.508 2.904 ;
     RECT  9.685 5.568 10.508 6.696 ;
     RECT  9.889 8.544 10.508 10.632 ;
     RECT  10.268 12.096 10.508 12.12 ;
     RECT  8.867 13.776 10.508 13.8 ;
     RECT  10.309 14.88 10.508 14.904 ;
     RECT  10.309 16.368 10.508 17.064 ;
     RECT  10.357 18.144 10.508 20.136 ;
     RECT  10.357 21.312 10.508 23.4 ;
     RECT  9.853 24.48 10.508 24.504 ;
     RECT  10.261 25.68 10.508 25.704 ;
     RECT  10.241 26.736 10.508 26.76 ;
     RECT  10.261 28.752 10.508 30.552 ;
     RECT  8.849 31.92 10.508 31.944 ;
     RECT  10.213 34.8 10.508 37.608 ;
     RECT  10.028 39.024 10.508 39.24 ;
     RECT  10.069 40.272 10.508 40.296 ;
     RECT  10.349 42 10.508 42.696 ;
     RECT  10.316 44.016 10.508 45.576 ;
     RECT  10.357 46.656 10.508 48.456 ;
     RECT  10.357 49.488 10.508 49.512 ;
     RECT  10.357 51.024 10.508 54.12 ;
     RECT  9.829 57.552 10.508 58.152 ;
     RECT  9.817 59.28 10.508 59.304 ;
     RECT  10.508 2.148 10.612 62.652 ;
     RECT  10.612 2.418 10.804 62.382 ;
     RECT  10.804 32.256 11.369 32.472 ;
     RECT  10.804 47.424 11.477 47.448 ;
     RECT  11.369 32.256 11.585 32.424 ;
     RECT  11.585 32.256 11.801 32.28 ;
     RECT  12.589 32.4 12.805 32.424 ;
     RECT  12.805 31.584 13.057 32.424 ;
     RECT  13.057 30.288 13.093 33.192 ;
     RECT  13.057 57.792 13.381 57.816 ;
     RECT  13.093 30.288 13.489 34.248 ;
     RECT  13.489 14.544 13.525 14.568 ;
     RECT  13.489 42.336 13.525 42.36 ;
     RECT  13.525 24 13.561 24.024 ;
     RECT  13.057 27.168 13.561 27.192 ;
     RECT  13.489 30.288 13.561 35.016 ;
     RECT  13.525 50.208 13.561 51 ;
     RECT  12.661 52.032 13.561 52.056 ;
     RECT  12.193 10.896 13.597 10.92 ;
     RECT  13.561 23.232 13.597 24.552 ;
     RECT  13.057 36.576 13.597 36.6 ;
     RECT  13.525 42.096 13.597 42.36 ;
     RECT  13.057 47.328 13.597 47.352 ;
     RECT  13.561 50.208 13.597 52.056 ;
     RECT  13.597 10.608 13.633 10.92 ;
     RECT  12.373 13.008 13.633 13.032 ;
     RECT  13.525 14.304 13.633 14.568 ;
     RECT  12.589 17.424 13.633 17.448 ;
     RECT  13.057 20.592 13.633 20.616 ;
     RECT  13.597 22.416 13.633 25.08 ;
     RECT  13.561 27.168 13.633 27.672 ;
     RECT  13.561 29.76 13.633 35.016 ;
     RECT  13.597 36.576 13.633 37.416 ;
     RECT  13.057 41.04 13.633 41.064 ;
     RECT  13.597 42.096 13.633 43.176 ;
     RECT  13.597 46.8 13.633 47.352 ;
     RECT  13.597 49.68 13.633 52.056 ;
     RECT  13.525 54.144 13.633 54.168 ;
     RECT  13.057 55.44 13.633 55.464 ;
     RECT  13.381 57.792 13.633 58.344 ;
     RECT  12.661 6.432 13.669 6.456 ;
     RECT  13.633 12.192 13.669 14.856 ;
     RECT  13.633 27.168 13.669 39.24 ;
     RECT  13.633 49.152 14.137 55.464 ;
     RECT  13.633 8.784 14.173 11.16 ;
     RECT  13.669 12.192 14.173 15.096 ;
     RECT  13.633 19.536 14.173 20.616 ;
     RECT  13.633 21.648 14.173 26.136 ;
     RECT  13.669 27.168 14.173 40.008 ;
     RECT  13.633 41.04 14.173 47.592 ;
     RECT  14.137 48.912 14.173 55.464 ;
     RECT  13.633 57.024 14.173 58.344 ;
     RECT  13.669 6.192 14.209 6.456 ;
     RECT  13.633 7.728 14.209 7.752 ;
     RECT  14.173 8.784 14.209 15.096 ;
     RECT  13.633 16.128 14.209 18.264 ;
     RECT  14.173 19.536 14.209 47.592 ;
     RECT  14.173 48.624 14.209 58.344 ;
     RECT  14.209 5.664 14.893 58.344 ;
     RECT  14.857 59.376 14.893 59.4 ;
     RECT  14.893 5.664 14.929 59.4 ;
     RECT  14.929 5.424 15.036 59.4 ;
    LAYER M5 ;
     RECT  0.192 1.285 0.216 1.381 ;
     RECT  0.096 1.381 0.216 1.427 ;
     RECT  2.4 2.137 2.52 2.151 ;
     RECT  5.1 2.137 5.22 2.151 ;
     RECT  7.8 2.137 7.92 2.151 ;
     RECT  9.696 2.137 10.62 2.151 ;
     RECT  9.696 2.151 10.812 2.915 ;
     RECT  7.8 2.151 8.112 5.557 ;
     RECT  9.792 2.915 10.812 5.653 ;
     RECT  7.392 5.557 8.112 6.181 ;
     RECT  5.1 2.151 5.412 7.381 ;
     RECT  7.2 6.181 8.112 7.957 ;
     RECT  9.696 5.653 10.812 7.957 ;
     RECT  7.2 7.957 10.812 8.579 ;
     RECT  9.936 8.579 10.812 8.819 ;
     RECT  3.936 7.909 3.96 9.155 ;
     RECT  10.272 8.819 10.812 9.731 ;
     RECT  5.1 7.381 5.688 10.069 ;
     RECT  7.2 8.579 8.856 10.355 ;
     RECT  4.512 10.069 5.688 10.883 ;
     RECT  7.8 10.355 8.856 10.883 ;
     RECT  4.896 10.883 5.688 13.139 ;
     RECT  7.8 10.883 8.112 13.141 ;
     RECT  7.2 13.141 8.112 13.621 ;
     RECT  4.992 13.139 5.688 13.715 ;
     RECT  7.2 13.621 8.232 14.197 ;
     RECT  7.2 14.197 8.856 14.387 ;
     RECT  4.992 13.715 5.412 14.867 ;
     RECT  7.8 14.387 8.856 14.867 ;
     RECT  2.4 2.151 2.712 15.301 ;
     RECT  3.936 13.429 3.96 15.301 ;
     RECT  2.4 15.301 3.96 15.443 ;
     RECT  5.1 14.867 5.412 15.829 ;
     RECT  10.32 9.731 10.812 16.931 ;
     RECT  2.4 15.443 3.144 17.123 ;
     RECT  5.1 15.829 5.688 18.851 ;
     RECT  10.368 16.931 10.812 19.333 ;
     RECT  7.8 14.867 8.232 19.861 ;
     RECT  9.552 19.333 10.812 20.147 ;
     RECT  7.68 19.861 8.232 20.389 ;
     RECT  7.2 20.389 8.232 20.485 ;
     RECT  5.1 18.851 5.412 20.869 ;
     RECT  7.2 20.485 8.856 21.683 ;
     RECT  7.68 21.683 8.856 21.731 ;
     RECT  7.68 21.731 8.112 23.317 ;
     RECT  10.368 20.147 10.812 23.411 ;
     RECT  7.632 23.317 8.112 23.893 ;
     RECT  10.5 23.411 10.812 24.469 ;
     RECT  10.272 24.469 10.812 25.715 ;
     RECT  5.1 20.869 5.688 26.291 ;
     RECT  10.5 25.715 10.812 26.725 ;
     RECT  7.2 23.893 8.112 28.211 ;
     RECT  5.1 26.291 5.64 28.405 ;
     RECT  7.632 28.211 8.112 30.133 ;
     RECT  0.096 1.427 0.12 30.229 ;
     RECT  0.096 30.229 0.264 30.275 ;
     RECT  0.24 30.275 0.264 30.419 ;
     RECT  10.272 26.725 10.812 30.517 ;
     RECT  4.992 28.405 5.64 30.565 ;
     RECT  3.936 21.397 3.96 30.851 ;
     RECT  7.248 30.133 8.856 30.851 ;
     RECT  4.944 30.565 5.64 31.379 ;
     RECT  2.4 17.123 2.712 31.765 ;
     RECT  10.176 30.517 10.812 31.955 ;
     RECT  2.4 31.765 3.672 32.437 ;
     RECT  7.248 30.851 8.112 33.013 ;
     RECT  4.944 31.379 5.412 34.259 ;
     RECT  7.248 33.013 8.952 34.355 ;
     RECT  2.4 32.437 3.96 34.835 ;
     RECT  10.5 31.955 10.812 34.933 ;
     RECT  3.696 34.835 3.96 35.939 ;
     RECT  10.224 34.933 10.812 35.939 ;
     RECT  7.632 34.355 8.952 36.085 ;
     RECT  5.1 34.259 5.412 37.573 ;
     RECT  10.5 35.939 10.812 37.573 ;
     RECT  3.696 35.939 3.72 37.667 ;
     RECT  10.08 37.573 10.812 40.307 ;
     RECT  2.4 34.835 2.712 42.469 ;
     RECT  10.5 40.307 10.812 42.661 ;
     RECT  7.2 36.085 8.952 42.803 ;
     RECT  7.344 42.803 8.952 43.861 ;
     RECT  10.368 42.661 10.812 44.051 ;
     RECT  2.4 42.469 3.336 44.483 ;
     RECT  5.1 37.573 5.688 46.259 ;
     RECT  3.936 45.205 3.96 46.309 ;
     RECT  3.888 46.309 3.96 46.501 ;
     RECT  5.1 46.259 5.412 46.501 ;
     RECT  7.2 43.861 8.952 46.787 ;
     RECT  3.888 46.501 5.412 47.363 ;
     RECT  7.344 46.787 8.952 47.363 ;
     RECT  10.5 44.051 10.812 47.701 ;
     RECT  3.936 47.363 5.412 47.845 ;
     RECT  3.936 47.845 5.688 47.939 ;
     RECT  7.8 47.363 8.952 48.275 ;
     RECT  3.936 47.939 3.96 48.421 ;
     RECT  7.8 48.275 8.856 48.997 ;
     RECT  3.888 48.421 3.96 49.619 ;
     RECT  4.944 47.939 5.688 49.765 ;
     RECT  7.248 48.997 8.856 50.771 ;
     RECT  4.512 49.765 5.688 51.109 ;
     RECT  3.936 51.109 5.688 51.205 ;
     RECT  3.888 51.205 5.688 51.347 ;
     RECT  3.888 51.347 3.96 51.923 ;
     RECT  3.888 51.923 3.912 52.019 ;
     RECT  5.1 51.347 5.688 52.357 ;
     RECT  2.4 44.483 2.712 53.509 ;
     RECT  5.1 52.357 6.264 53.603 ;
     RECT  5.1 53.603 5.688 53.651 ;
     RECT  10.368 47.701 10.812 54.131 ;
     RECT  2.4 53.509 3.432 54.179 ;
     RECT  7.248 50.771 8.112 54.949 ;
     RECT  7.248 54.949 8.856 55.237 ;
     RECT  5.1 53.651 5.412 55.765 ;
     RECT  7.2 55.237 8.856 57.539 ;
     RECT  10.5 54.131 10.812 57.541 ;
     RECT  7.8 57.539 8.856 57.587 ;
     RECT  9.84 57.541 10.812 59.315 ;
     RECT  4.8 55.765 5.412 59.507 ;
     RECT  2.4 54.179 2.712 62.649 ;
     RECT  5.1 59.507 5.412 62.649 ;
     RECT  7.8 57.587 8.112 62.649 ;
     RECT  10.5 59.315 10.812 62.649 ;
     RECT  2.4 62.649 2.52 62.663 ;
     RECT  5.1 62.649 5.22 62.663 ;
     RECT  7.8 62.649 7.92 62.663 ;
     RECT  10.5 62.649 10.62 62.663 ;
     RECT  5.688 7.381 7.2 10.355 ;
     RECT  2.712 7.909 3.936 9.155 ;
     RECT  3.96 7.909 5.1 9.155 ;
     RECT  8.856 8.579 9.936 8.819 ;
     RECT  8.856 8.819 10.272 9.731 ;
     RECT  4.512 9.155 5.1 10.069 ;
     RECT  8.856 9.731 10.32 10.883 ;
     RECT  4.896 13.139 4.992 13.429 ;
     RECT  5.688 13.141 7.2 13.715 ;
     RECT  2.712 13.429 3.936 15.301 ;
     RECT  3.96 13.429 4.992 14.867 ;
     RECT  8.856 14.197 10.32 14.867 ;
     RECT  3.96 14.867 5.1 15.443 ;
     RECT  8.232 19.333 9.552 20.147 ;
     RECT  8.232 20.147 10.368 20.485 ;
     RECT  8.856 20.485 10.368 21.731 ;
     RECT  5.688 20.869 7.2 21.683 ;
     RECT  2.712 21.397 3.936 30.851 ;
     RECT  3.96 21.397 5.1 28.405 ;
     RECT  10.368 23.411 10.5 24.469 ;
     RECT  5.688 23.893 7.2 26.291 ;
     RECT  10.272 25.715 10.5 26.725 ;
     RECT  3.96 28.405 4.992 30.565 ;
     RECT  8.856 30.133 10.272 30.517 ;
     RECT  8.856 30.517 10.176 30.851 ;
     RECT  3.96 30.565 4.944 30.851 ;
     RECT  2.712 30.851 4.944 31.765 ;
     RECT  3.672 31.765 4.944 32.437 ;
     RECT  3.96 32.437 4.944 34.259 ;
     RECT  3.96 34.259 5.1 35.939 ;
     RECT  2.712 34.835 3.696 37.667 ;
     RECT  8.952 34.933 10.224 35.939 ;
     RECT  3.72 35.939 5.1 37.667 ;
     RECT  5.688 37.573 7.2 42.803 ;
     RECT  8.952 37.573 10.08 40.307 ;
     RECT  8.952 42.661 10.368 44.051 ;
     RECT  5.688 42.803 7.344 43.861 ;
     RECT  5.688 43.861 7.2 46.259 ;
     RECT  2.712 44.483 3.336 45.205 ;
     RECT  2.712 45.205 3.936 46.309 ;
     RECT  3.96 45.205 5.1 46.501 ;
     RECT  2.712 46.309 3.888 47.363 ;
     RECT  2.712 47.363 3.936 48.421 ;
     RECT  8.952 47.701 10.368 48.275 ;
     RECT  3.96 47.939 4.944 49.619 ;
     RECT  8.856 48.275 10.368 50.771 ;
     RECT  2.712 48.421 3.888 49.619 ;
     RECT  2.712 49.619 4.944 49.765 ;
     RECT  2.712 49.765 4.512 51.109 ;
     RECT  2.712 51.109 3.936 51.205 ;
     RECT  2.712 51.205 3.888 52.019 ;
     RECT  3.96 51.347 5.1 51.923 ;
     RECT  3.912 51.923 5.1 52.019 ;
     RECT  2.712 52.019 3.432 53.509 ;
     RECT  6.264 52.357 7.248 53.603 ;
     RECT  8.856 57.541 9.84 57.587 ;
  END
END qwen_tx_rne_r0
END LIBRARY
